# Generated by FakeRAM 2.0
VERSION 5.7 ;
BUSBITCHARS "[]" ;
PROPERTYDEFINITIONS
  MACRO width INTEGER ;
  MACRO depth INTEGER ;
  MACRO banks INTEGER ;
END PROPERTYDEFINITIONS
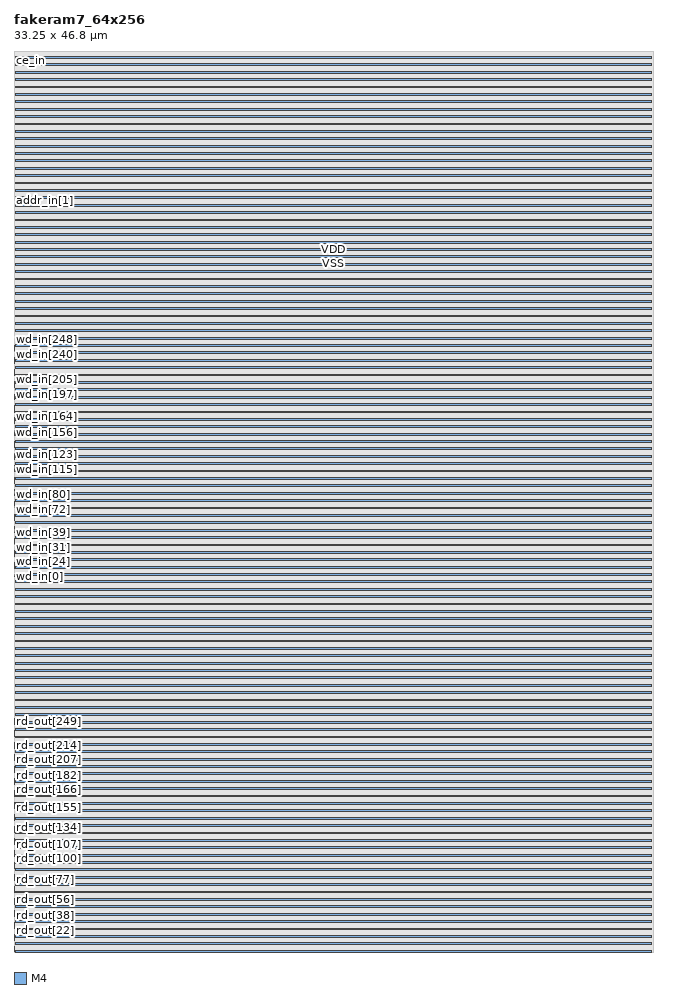
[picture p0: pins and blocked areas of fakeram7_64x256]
MACRO fakeram7_64x256
  PROPERTY width 256 ;
  PROPERTY depth 64 ;
  PROPERTY banks 1 ;
  FOREIGN fakeram7_64x256 0 0 ;
  SYMMETRY X Y R90 ;
  SIZE 33.250 BY 46.800 ;
  CLASS BLOCK ;
  PIN rd_out[0]
    DIRECTION OUTPUT ;
    USE SIGNAL ;
    SHAPE ABUTMENT ;
    PORT
      LAYER M4 ;
      RECT 0.000 0.048 0.036 0.072 ;
    END
  END rd_out[0]
  PIN rd_out[1]
    DIRECTION OUTPUT ;
    USE SIGNAL ;
    SHAPE ABUTMENT ;
    PORT
      LAYER M4 ;
      RECT 0.000 0.096 0.036 0.120 ;
    END
  END rd_out[1]
  PIN rd_out[2]
    DIRECTION OUTPUT ;
    USE SIGNAL ;
    SHAPE ABUTMENT ;
    PORT
      LAYER M4 ;
      RECT 0.000 0.144 0.036 0.168 ;
    END
  END rd_out[2]
  PIN rd_out[3]
    DIRECTION OUTPUT ;
    USE SIGNAL ;
    SHAPE ABUTMENT ;
    PORT
      LAYER M4 ;
      RECT 0.000 0.192 0.036 0.216 ;
    END
  END rd_out[3]
  PIN rd_out[4]
    DIRECTION OUTPUT ;
    USE SIGNAL ;
    SHAPE ABUTMENT ;
    PORT
      LAYER M4 ;
      RECT 0.000 0.240 0.036 0.264 ;
    END
  END rd_out[4]
  PIN rd_out[5]
    DIRECTION OUTPUT ;
    USE SIGNAL ;
    SHAPE ABUTMENT ;
    PORT
      LAYER M4 ;
      RECT 0.000 0.288 0.036 0.312 ;
    END
  END rd_out[5]
  PIN rd_out[6]
    DIRECTION OUTPUT ;
    USE SIGNAL ;
    SHAPE ABUTMENT ;
    PORT
      LAYER M4 ;
      RECT 0.000 0.336 0.036 0.360 ;
    END
  END rd_out[6]
  PIN rd_out[7]
    DIRECTION OUTPUT ;
    USE SIGNAL ;
    SHAPE ABUTMENT ;
    PORT
      LAYER M4 ;
      RECT 0.000 0.384 0.036 0.408 ;
    END
  END rd_out[7]
  PIN rd_out[8]
    DIRECTION OUTPUT ;
    USE SIGNAL ;
    SHAPE ABUTMENT ;
    PORT
      LAYER M4 ;
      RECT 0.000 0.432 0.036 0.456 ;
    END
  END rd_out[8]
  PIN rd_out[9]
    DIRECTION OUTPUT ;
    USE SIGNAL ;
    SHAPE ABUTMENT ;
    PORT
      LAYER M4 ;
      RECT 0.000 0.480 0.036 0.504 ;
    END
  END rd_out[9]
  PIN rd_out[10]
    DIRECTION OUTPUT ;
    USE SIGNAL ;
    SHAPE ABUTMENT ;
    PORT
      LAYER M4 ;
      RECT 0.000 0.528 0.036 0.552 ;
    END
  END rd_out[10]
  PIN rd_out[11]
    DIRECTION OUTPUT ;
    USE SIGNAL ;
    SHAPE ABUTMENT ;
    PORT
      LAYER M4 ;
      RECT 0.000 0.576 0.036 0.600 ;
    END
  END rd_out[11]
  PIN rd_out[12]
    DIRECTION OUTPUT ;
    USE SIGNAL ;
    SHAPE ABUTMENT ;
    PORT
      LAYER M4 ;
      RECT 0.000 0.624 0.036 0.648 ;
    END
  END rd_out[12]
  PIN rd_out[13]
    DIRECTION OUTPUT ;
    USE SIGNAL ;
    SHAPE ABUTMENT ;
    PORT
      LAYER M4 ;
      RECT 0.000 0.672 0.036 0.696 ;
    END
  END rd_out[13]
  PIN rd_out[14]
    DIRECTION OUTPUT ;
    USE SIGNAL ;
    SHAPE ABUTMENT ;
    PORT
      LAYER M4 ;
      RECT 0.000 0.720 0.036 0.744 ;
    END
  END rd_out[14]
  PIN rd_out[15]
    DIRECTION OUTPUT ;
    USE SIGNAL ;
    SHAPE ABUTMENT ;
    PORT
      LAYER M4 ;
      RECT 0.000 0.768 0.036 0.792 ;
    END
  END rd_out[15]
  PIN rd_out[16]
    DIRECTION OUTPUT ;
    USE SIGNAL ;
    SHAPE ABUTMENT ;
    PORT
      LAYER M4 ;
      RECT 0.000 0.816 0.036 0.840 ;
    END
  END rd_out[16]
  PIN rd_out[17]
    DIRECTION OUTPUT ;
    USE SIGNAL ;
    SHAPE ABUTMENT ;
    PORT
      LAYER M4 ;
      RECT 0.000 0.864 0.036 0.888 ;
    END
  END rd_out[17]
  PIN rd_out[18]
    DIRECTION OUTPUT ;
    USE SIGNAL ;
    SHAPE ABUTMENT ;
    PORT
      LAYER M4 ;
      RECT 0.000 0.912 0.036 0.936 ;
    END
  END rd_out[18]
  PIN rd_out[19]
    DIRECTION OUTPUT ;
    USE SIGNAL ;
    SHAPE ABUTMENT ;
    PORT
      LAYER M4 ;
      RECT 0.000 0.960 0.036 0.984 ;
    END
  END rd_out[19]
  PIN rd_out[20]
    DIRECTION OUTPUT ;
    USE SIGNAL ;
    SHAPE ABUTMENT ;
    PORT
      LAYER M4 ;
      RECT 0.000 1.008 0.036 1.032 ;
    END
  END rd_out[20]
  PIN rd_out[21]
    DIRECTION OUTPUT ;
    USE SIGNAL ;
    SHAPE ABUTMENT ;
    PORT
      LAYER M4 ;
      RECT 0.000 1.056 0.036 1.080 ;
    END
  END rd_out[21]
  PIN rd_out[22]
    DIRECTION OUTPUT ;
    USE SIGNAL ;
    SHAPE ABUTMENT ;
    PORT
      LAYER M4 ;
      RECT 0.000 1.104 0.036 1.128 ;
    END
  END rd_out[22]
  PIN rd_out[23]
    DIRECTION OUTPUT ;
    USE SIGNAL ;
    SHAPE ABUTMENT ;
    PORT
      LAYER M4 ;
      RECT 0.000 1.152 0.036 1.176 ;
    END
  END rd_out[23]
  PIN rd_out[24]
    DIRECTION OUTPUT ;
    USE SIGNAL ;
    SHAPE ABUTMENT ;
    PORT
      LAYER M4 ;
      RECT 0.000 1.200 0.036 1.224 ;
    END
  END rd_out[24]
  PIN rd_out[25]
    DIRECTION OUTPUT ;
    USE SIGNAL ;
    SHAPE ABUTMENT ;
    PORT
      LAYER M4 ;
      RECT 0.000 1.248 0.036 1.272 ;
    END
  END rd_out[25]
  PIN rd_out[26]
    DIRECTION OUTPUT ;
    USE SIGNAL ;
    SHAPE ABUTMENT ;
    PORT
      LAYER M4 ;
      RECT 0.000 1.296 0.036 1.320 ;
    END
  END rd_out[26]
  PIN rd_out[27]
    DIRECTION OUTPUT ;
    USE SIGNAL ;
    SHAPE ABUTMENT ;
    PORT
      LAYER M4 ;
      RECT 0.000 1.344 0.036 1.368 ;
    END
  END rd_out[27]
  PIN rd_out[28]
    DIRECTION OUTPUT ;
    USE SIGNAL ;
    SHAPE ABUTMENT ;
    PORT
      LAYER M4 ;
      RECT 0.000 1.392 0.036 1.416 ;
    END
  END rd_out[28]
  PIN rd_out[29]
    DIRECTION OUTPUT ;
    USE SIGNAL ;
    SHAPE ABUTMENT ;
    PORT
      LAYER M4 ;
      RECT 0.000 1.440 0.036 1.464 ;
    END
  END rd_out[29]
  PIN rd_out[30]
    DIRECTION OUTPUT ;
    USE SIGNAL ;
    SHAPE ABUTMENT ;
    PORT
      LAYER M4 ;
      RECT 0.000 1.488 0.036 1.512 ;
    END
  END rd_out[30]
  PIN rd_out[31]
    DIRECTION OUTPUT ;
    USE SIGNAL ;
    SHAPE ABUTMENT ;
    PORT
      LAYER M4 ;
      RECT 0.000 1.536 0.036 1.560 ;
    END
  END rd_out[31]
  PIN rd_out[32]
    DIRECTION OUTPUT ;
    USE SIGNAL ;
    SHAPE ABUTMENT ;
    PORT
      LAYER M4 ;
      RECT 0.000 1.584 0.036 1.608 ;
    END
  END rd_out[32]
  PIN rd_out[33]
    DIRECTION OUTPUT ;
    USE SIGNAL ;
    SHAPE ABUTMENT ;
    PORT
      LAYER M4 ;
      RECT 0.000 1.632 0.036 1.656 ;
    END
  END rd_out[33]
  PIN rd_out[34]
    DIRECTION OUTPUT ;
    USE SIGNAL ;
    SHAPE ABUTMENT ;
    PORT
      LAYER M4 ;
      RECT 0.000 1.680 0.036 1.704 ;
    END
  END rd_out[34]
  PIN rd_out[35]
    DIRECTION OUTPUT ;
    USE SIGNAL ;
    SHAPE ABUTMENT ;
    PORT
      LAYER M4 ;
      RECT 0.000 1.728 0.036 1.752 ;
    END
  END rd_out[35]
  PIN rd_out[36]
    DIRECTION OUTPUT ;
    USE SIGNAL ;
    SHAPE ABUTMENT ;
    PORT
      LAYER M4 ;
      RECT 0.000 1.776 0.036 1.800 ;
    END
  END rd_out[36]
  PIN rd_out[37]
    DIRECTION OUTPUT ;
    USE SIGNAL ;
    SHAPE ABUTMENT ;
    PORT
      LAYER M4 ;
      RECT 0.000 1.824 0.036 1.848 ;
    END
  END rd_out[37]
  PIN rd_out[38]
    DIRECTION OUTPUT ;
    USE SIGNAL ;
    SHAPE ABUTMENT ;
    PORT
      LAYER M4 ;
      RECT 0.000 1.872 0.036 1.896 ;
    END
  END rd_out[38]
  PIN rd_out[39]
    DIRECTION OUTPUT ;
    USE SIGNAL ;
    SHAPE ABUTMENT ;
    PORT
      LAYER M4 ;
      RECT 0.000 1.920 0.036 1.944 ;
    END
  END rd_out[39]
  PIN rd_out[40]
    DIRECTION OUTPUT ;
    USE SIGNAL ;
    SHAPE ABUTMENT ;
    PORT
      LAYER M4 ;
      RECT 0.000 1.968 0.036 1.992 ;
    END
  END rd_out[40]
  PIN rd_out[41]
    DIRECTION OUTPUT ;
    USE SIGNAL ;
    SHAPE ABUTMENT ;
    PORT
      LAYER M4 ;
      RECT 0.000 2.016 0.036 2.040 ;
    END
  END rd_out[41]
  PIN rd_out[42]
    DIRECTION OUTPUT ;
    USE SIGNAL ;
    SHAPE ABUTMENT ;
    PORT
      LAYER M4 ;
      RECT 0.000 2.064 0.036 2.088 ;
    END
  END rd_out[42]
  PIN rd_out[43]
    DIRECTION OUTPUT ;
    USE SIGNAL ;
    SHAPE ABUTMENT ;
    PORT
      LAYER M4 ;
      RECT 0.000 2.112 0.036 2.136 ;
    END
  END rd_out[43]
  PIN rd_out[44]
    DIRECTION OUTPUT ;
    USE SIGNAL ;
    SHAPE ABUTMENT ;
    PORT
      LAYER M4 ;
      RECT 0.000 2.160 0.036 2.184 ;
    END
  END rd_out[44]
  PIN rd_out[45]
    DIRECTION OUTPUT ;
    USE SIGNAL ;
    SHAPE ABUTMENT ;
    PORT
      LAYER M4 ;
      RECT 0.000 2.208 0.036 2.232 ;
    END
  END rd_out[45]
  PIN rd_out[46]
    DIRECTION OUTPUT ;
    USE SIGNAL ;
    SHAPE ABUTMENT ;
    PORT
      LAYER M4 ;
      RECT 0.000 2.256 0.036 2.280 ;
    END
  END rd_out[46]
  PIN rd_out[47]
    DIRECTION OUTPUT ;
    USE SIGNAL ;
    SHAPE ABUTMENT ;
    PORT
      LAYER M4 ;
      RECT 0.000 2.304 0.036 2.328 ;
    END
  END rd_out[47]
  PIN rd_out[48]
    DIRECTION OUTPUT ;
    USE SIGNAL ;
    SHAPE ABUTMENT ;
    PORT
      LAYER M4 ;
      RECT 0.000 2.352 0.036 2.376 ;
    END
  END rd_out[48]
  PIN rd_out[49]
    DIRECTION OUTPUT ;
    USE SIGNAL ;
    SHAPE ABUTMENT ;
    PORT
      LAYER M4 ;
      RECT 0.000 2.400 0.036 2.424 ;
    END
  END rd_out[49]
  PIN rd_out[50]
    DIRECTION OUTPUT ;
    USE SIGNAL ;
    SHAPE ABUTMENT ;
    PORT
      LAYER M4 ;
      RECT 0.000 2.448 0.036 2.472 ;
    END
  END rd_out[50]
  PIN rd_out[51]
    DIRECTION OUTPUT ;
    USE SIGNAL ;
    SHAPE ABUTMENT ;
    PORT
      LAYER M4 ;
      RECT 0.000 2.496 0.036 2.520 ;
    END
  END rd_out[51]
  PIN rd_out[52]
    DIRECTION OUTPUT ;
    USE SIGNAL ;
    SHAPE ABUTMENT ;
    PORT
      LAYER M4 ;
      RECT 0.000 2.544 0.036 2.568 ;
    END
  END rd_out[52]
  PIN rd_out[53]
    DIRECTION OUTPUT ;
    USE SIGNAL ;
    SHAPE ABUTMENT ;
    PORT
      LAYER M4 ;
      RECT 0.000 2.592 0.036 2.616 ;
    END
  END rd_out[53]
  PIN rd_out[54]
    DIRECTION OUTPUT ;
    USE SIGNAL ;
    SHAPE ABUTMENT ;
    PORT
      LAYER M4 ;
      RECT 0.000 2.640 0.036 2.664 ;
    END
  END rd_out[54]
  PIN rd_out[55]
    DIRECTION OUTPUT ;
    USE SIGNAL ;
    SHAPE ABUTMENT ;
    PORT
      LAYER M4 ;
      RECT 0.000 2.688 0.036 2.712 ;
    END
  END rd_out[55]
  PIN rd_out[56]
    DIRECTION OUTPUT ;
    USE SIGNAL ;
    SHAPE ABUTMENT ;
    PORT
      LAYER M4 ;
      RECT 0.000 2.736 0.036 2.760 ;
    END
  END rd_out[56]
  PIN rd_out[57]
    DIRECTION OUTPUT ;
    USE SIGNAL ;
    SHAPE ABUTMENT ;
    PORT
      LAYER M4 ;
      RECT 0.000 2.784 0.036 2.808 ;
    END
  END rd_out[57]
  PIN rd_out[58]
    DIRECTION OUTPUT ;
    USE SIGNAL ;
    SHAPE ABUTMENT ;
    PORT
      LAYER M4 ;
      RECT 0.000 2.832 0.036 2.856 ;
    END
  END rd_out[58]
  PIN rd_out[59]
    DIRECTION OUTPUT ;
    USE SIGNAL ;
    SHAPE ABUTMENT ;
    PORT
      LAYER M4 ;
      RECT 0.000 2.880 0.036 2.904 ;
    END
  END rd_out[59]
  PIN rd_out[60]
    DIRECTION OUTPUT ;
    USE SIGNAL ;
    SHAPE ABUTMENT ;
    PORT
      LAYER M4 ;
      RECT 0.000 2.928 0.036 2.952 ;
    END
  END rd_out[60]
  PIN rd_out[61]
    DIRECTION OUTPUT ;
    USE SIGNAL ;
    SHAPE ABUTMENT ;
    PORT
      LAYER M4 ;
      RECT 0.000 2.976 0.036 3.000 ;
    END
  END rd_out[61]
  PIN rd_out[62]
    DIRECTION OUTPUT ;
    USE SIGNAL ;
    SHAPE ABUTMENT ;
    PORT
      LAYER M4 ;
      RECT 0.000 3.024 0.036 3.048 ;
    END
  END rd_out[62]
  PIN rd_out[63]
    DIRECTION OUTPUT ;
    USE SIGNAL ;
    SHAPE ABUTMENT ;
    PORT
      LAYER M4 ;
      RECT 0.000 3.072 0.036 3.096 ;
    END
  END rd_out[63]
  PIN rd_out[64]
    DIRECTION OUTPUT ;
    USE SIGNAL ;
    SHAPE ABUTMENT ;
    PORT
      LAYER M4 ;
      RECT 0.000 3.120 0.036 3.144 ;
    END
  END rd_out[64]
  PIN rd_out[65]
    DIRECTION OUTPUT ;
    USE SIGNAL ;
    SHAPE ABUTMENT ;
    PORT
      LAYER M4 ;
      RECT 0.000 3.168 0.036 3.192 ;
    END
  END rd_out[65]
  PIN rd_out[66]
    DIRECTION OUTPUT ;
    USE SIGNAL ;
    SHAPE ABUTMENT ;
    PORT
      LAYER M4 ;
      RECT 0.000 3.216 0.036 3.240 ;
    END
  END rd_out[66]
  PIN rd_out[67]
    DIRECTION OUTPUT ;
    USE SIGNAL ;
    SHAPE ABUTMENT ;
    PORT
      LAYER M4 ;
      RECT 0.000 3.264 0.036 3.288 ;
    END
  END rd_out[67]
  PIN rd_out[68]
    DIRECTION OUTPUT ;
    USE SIGNAL ;
    SHAPE ABUTMENT ;
    PORT
      LAYER M4 ;
      RECT 0.000 3.312 0.036 3.336 ;
    END
  END rd_out[68]
  PIN rd_out[69]
    DIRECTION OUTPUT ;
    USE SIGNAL ;
    SHAPE ABUTMENT ;
    PORT
      LAYER M4 ;
      RECT 0.000 3.360 0.036 3.384 ;
    END
  END rd_out[69]
  PIN rd_out[70]
    DIRECTION OUTPUT ;
    USE SIGNAL ;
    SHAPE ABUTMENT ;
    PORT
      LAYER M4 ;
      RECT 0.000 3.408 0.036 3.432 ;
    END
  END rd_out[70]
  PIN rd_out[71]
    DIRECTION OUTPUT ;
    USE SIGNAL ;
    SHAPE ABUTMENT ;
    PORT
      LAYER M4 ;
      RECT 0.000 3.456 0.036 3.480 ;
    END
  END rd_out[71]
  PIN rd_out[72]
    DIRECTION OUTPUT ;
    USE SIGNAL ;
    SHAPE ABUTMENT ;
    PORT
      LAYER M4 ;
      RECT 0.000 3.504 0.036 3.528 ;
    END
  END rd_out[72]
  PIN rd_out[73]
    DIRECTION OUTPUT ;
    USE SIGNAL ;
    SHAPE ABUTMENT ;
    PORT
      LAYER M4 ;
      RECT 0.000 3.552 0.036 3.576 ;
    END
  END rd_out[73]
  PIN rd_out[74]
    DIRECTION OUTPUT ;
    USE SIGNAL ;
    SHAPE ABUTMENT ;
    PORT
      LAYER M4 ;
      RECT 0.000 3.600 0.036 3.624 ;
    END
  END rd_out[74]
  PIN rd_out[75]
    DIRECTION OUTPUT ;
    USE SIGNAL ;
    SHAPE ABUTMENT ;
    PORT
      LAYER M4 ;
      RECT 0.000 3.648 0.036 3.672 ;
    END
  END rd_out[75]
  PIN rd_out[76]
    DIRECTION OUTPUT ;
    USE SIGNAL ;
    SHAPE ABUTMENT ;
    PORT
      LAYER M4 ;
      RECT 0.000 3.696 0.036 3.720 ;
    END
  END rd_out[76]
  PIN rd_out[77]
    DIRECTION OUTPUT ;
    USE SIGNAL ;
    SHAPE ABUTMENT ;
    PORT
      LAYER M4 ;
      RECT 0.000 3.744 0.036 3.768 ;
    END
  END rd_out[77]
  PIN rd_out[78]
    DIRECTION OUTPUT ;
    USE SIGNAL ;
    SHAPE ABUTMENT ;
    PORT
      LAYER M4 ;
      RECT 0.000 3.792 0.036 3.816 ;
    END
  END rd_out[78]
  PIN rd_out[79]
    DIRECTION OUTPUT ;
    USE SIGNAL ;
    SHAPE ABUTMENT ;
    PORT
      LAYER M4 ;
      RECT 0.000 3.840 0.036 3.864 ;
    END
  END rd_out[79]
  PIN rd_out[80]
    DIRECTION OUTPUT ;
    USE SIGNAL ;
    SHAPE ABUTMENT ;
    PORT
      LAYER M4 ;
      RECT 0.000 3.888 0.036 3.912 ;
    END
  END rd_out[80]
  PIN rd_out[81]
    DIRECTION OUTPUT ;
    USE SIGNAL ;
    SHAPE ABUTMENT ;
    PORT
      LAYER M4 ;
      RECT 0.000 3.936 0.036 3.960 ;
    END
  END rd_out[81]
  PIN rd_out[82]
    DIRECTION OUTPUT ;
    USE SIGNAL ;
    SHAPE ABUTMENT ;
    PORT
      LAYER M4 ;
      RECT 0.000 3.984 0.036 4.008 ;
    END
  END rd_out[82]
  PIN rd_out[83]
    DIRECTION OUTPUT ;
    USE SIGNAL ;
    SHAPE ABUTMENT ;
    PORT
      LAYER M4 ;
      RECT 0.000 4.032 0.036 4.056 ;
    END
  END rd_out[83]
  PIN rd_out[84]
    DIRECTION OUTPUT ;
    USE SIGNAL ;
    SHAPE ABUTMENT ;
    PORT
      LAYER M4 ;
      RECT 0.000 4.080 0.036 4.104 ;
    END
  END rd_out[84]
  PIN rd_out[85]
    DIRECTION OUTPUT ;
    USE SIGNAL ;
    SHAPE ABUTMENT ;
    PORT
      LAYER M4 ;
      RECT 0.000 4.128 0.036 4.152 ;
    END
  END rd_out[85]
  PIN rd_out[86]
    DIRECTION OUTPUT ;
    USE SIGNAL ;
    SHAPE ABUTMENT ;
    PORT
      LAYER M4 ;
      RECT 0.000 4.176 0.036 4.200 ;
    END
  END rd_out[86]
  PIN rd_out[87]
    DIRECTION OUTPUT ;
    USE SIGNAL ;
    SHAPE ABUTMENT ;
    PORT
      LAYER M4 ;
      RECT 0.000 4.224 0.036 4.248 ;
    END
  END rd_out[87]
  PIN rd_out[88]
    DIRECTION OUTPUT ;
    USE SIGNAL ;
    SHAPE ABUTMENT ;
    PORT
      LAYER M4 ;
      RECT 0.000 4.272 0.036 4.296 ;
    END
  END rd_out[88]
  PIN rd_out[89]
    DIRECTION OUTPUT ;
    USE SIGNAL ;
    SHAPE ABUTMENT ;
    PORT
      LAYER M4 ;
      RECT 0.000 4.320 0.036 4.344 ;
    END
  END rd_out[89]
  PIN rd_out[90]
    DIRECTION OUTPUT ;
    USE SIGNAL ;
    SHAPE ABUTMENT ;
    PORT
      LAYER M4 ;
      RECT 0.000 4.368 0.036 4.392 ;
    END
  END rd_out[90]
  PIN rd_out[91]
    DIRECTION OUTPUT ;
    USE SIGNAL ;
    SHAPE ABUTMENT ;
    PORT
      LAYER M4 ;
      RECT 0.000 4.416 0.036 4.440 ;
    END
  END rd_out[91]
  PIN rd_out[92]
    DIRECTION OUTPUT ;
    USE SIGNAL ;
    SHAPE ABUTMENT ;
    PORT
      LAYER M4 ;
      RECT 0.000 4.464 0.036 4.488 ;
    END
  END rd_out[92]
  PIN rd_out[93]
    DIRECTION OUTPUT ;
    USE SIGNAL ;
    SHAPE ABUTMENT ;
    PORT
      LAYER M4 ;
      RECT 0.000 4.512 0.036 4.536 ;
    END
  END rd_out[93]
  PIN rd_out[94]
    DIRECTION OUTPUT ;
    USE SIGNAL ;
    SHAPE ABUTMENT ;
    PORT
      LAYER M4 ;
      RECT 0.000 4.560 0.036 4.584 ;
    END
  END rd_out[94]
  PIN rd_out[95]
    DIRECTION OUTPUT ;
    USE SIGNAL ;
    SHAPE ABUTMENT ;
    PORT
      LAYER M4 ;
      RECT 0.000 4.608 0.036 4.632 ;
    END
  END rd_out[95]
  PIN rd_out[96]
    DIRECTION OUTPUT ;
    USE SIGNAL ;
    SHAPE ABUTMENT ;
    PORT
      LAYER M4 ;
      RECT 0.000 4.656 0.036 4.680 ;
    END
  END rd_out[96]
  PIN rd_out[97]
    DIRECTION OUTPUT ;
    USE SIGNAL ;
    SHAPE ABUTMENT ;
    PORT
      LAYER M4 ;
      RECT 0.000 4.704 0.036 4.728 ;
    END
  END rd_out[97]
  PIN rd_out[98]
    DIRECTION OUTPUT ;
    USE SIGNAL ;
    SHAPE ABUTMENT ;
    PORT
      LAYER M4 ;
      RECT 0.000 4.752 0.036 4.776 ;
    END
  END rd_out[98]
  PIN rd_out[99]
    DIRECTION OUTPUT ;
    USE SIGNAL ;
    SHAPE ABUTMENT ;
    PORT
      LAYER M4 ;
      RECT 0.000 4.800 0.036 4.824 ;
    END
  END rd_out[99]
  PIN rd_out[100]
    DIRECTION OUTPUT ;
    USE SIGNAL ;
    SHAPE ABUTMENT ;
    PORT
      LAYER M4 ;
      RECT 0.000 4.848 0.036 4.872 ;
    END
  END rd_out[100]
  PIN rd_out[101]
    DIRECTION OUTPUT ;
    USE SIGNAL ;
    SHAPE ABUTMENT ;
    PORT
      LAYER M4 ;
      RECT 0.000 4.896 0.036 4.920 ;
    END
  END rd_out[101]
  PIN rd_out[102]
    DIRECTION OUTPUT ;
    USE SIGNAL ;
    SHAPE ABUTMENT ;
    PORT
      LAYER M4 ;
      RECT 0.000 4.944 0.036 4.968 ;
    END
  END rd_out[102]
  PIN rd_out[103]
    DIRECTION OUTPUT ;
    USE SIGNAL ;
    SHAPE ABUTMENT ;
    PORT
      LAYER M4 ;
      RECT 0.000 4.992 0.036 5.016 ;
    END
  END rd_out[103]
  PIN rd_out[104]
    DIRECTION OUTPUT ;
    USE SIGNAL ;
    SHAPE ABUTMENT ;
    PORT
      LAYER M4 ;
      RECT 0.000 5.040 0.036 5.064 ;
    END
  END rd_out[104]
  PIN rd_out[105]
    DIRECTION OUTPUT ;
    USE SIGNAL ;
    SHAPE ABUTMENT ;
    PORT
      LAYER M4 ;
      RECT 0.000 5.088 0.036 5.112 ;
    END
  END rd_out[105]
  PIN rd_out[106]
    DIRECTION OUTPUT ;
    USE SIGNAL ;
    SHAPE ABUTMENT ;
    PORT
      LAYER M4 ;
      RECT 0.000 5.136 0.036 5.160 ;
    END
  END rd_out[106]
  PIN rd_out[107]
    DIRECTION OUTPUT ;
    USE SIGNAL ;
    SHAPE ABUTMENT ;
    PORT
      LAYER M4 ;
      RECT 0.000 5.184 0.036 5.208 ;
    END
  END rd_out[107]
  PIN rd_out[108]
    DIRECTION OUTPUT ;
    USE SIGNAL ;
    SHAPE ABUTMENT ;
    PORT
      LAYER M4 ;
      RECT 0.000 5.232 0.036 5.256 ;
    END
  END rd_out[108]
  PIN rd_out[109]
    DIRECTION OUTPUT ;
    USE SIGNAL ;
    SHAPE ABUTMENT ;
    PORT
      LAYER M4 ;
      RECT 0.000 5.280 0.036 5.304 ;
    END
  END rd_out[109]
  PIN rd_out[110]
    DIRECTION OUTPUT ;
    USE SIGNAL ;
    SHAPE ABUTMENT ;
    PORT
      LAYER M4 ;
      RECT 0.000 5.328 0.036 5.352 ;
    END
  END rd_out[110]
  PIN rd_out[111]
    DIRECTION OUTPUT ;
    USE SIGNAL ;
    SHAPE ABUTMENT ;
    PORT
      LAYER M4 ;
      RECT 0.000 5.376 0.036 5.400 ;
    END
  END rd_out[111]
  PIN rd_out[112]
    DIRECTION OUTPUT ;
    USE SIGNAL ;
    SHAPE ABUTMENT ;
    PORT
      LAYER M4 ;
      RECT 0.000 5.424 0.036 5.448 ;
    END
  END rd_out[112]
  PIN rd_out[113]
    DIRECTION OUTPUT ;
    USE SIGNAL ;
    SHAPE ABUTMENT ;
    PORT
      LAYER M4 ;
      RECT 0.000 5.472 0.036 5.496 ;
    END
  END rd_out[113]
  PIN rd_out[114]
    DIRECTION OUTPUT ;
    USE SIGNAL ;
    SHAPE ABUTMENT ;
    PORT
      LAYER M4 ;
      RECT 0.000 5.520 0.036 5.544 ;
    END
  END rd_out[114]
  PIN rd_out[115]
    DIRECTION OUTPUT ;
    USE SIGNAL ;
    SHAPE ABUTMENT ;
    PORT
      LAYER M4 ;
      RECT 0.000 5.568 0.036 5.592 ;
    END
  END rd_out[115]
  PIN rd_out[116]
    DIRECTION OUTPUT ;
    USE SIGNAL ;
    SHAPE ABUTMENT ;
    PORT
      LAYER M4 ;
      RECT 0.000 5.616 0.036 5.640 ;
    END
  END rd_out[116]
  PIN rd_out[117]
    DIRECTION OUTPUT ;
    USE SIGNAL ;
    SHAPE ABUTMENT ;
    PORT
      LAYER M4 ;
      RECT 0.000 5.664 0.036 5.688 ;
    END
  END rd_out[117]
  PIN rd_out[118]
    DIRECTION OUTPUT ;
    USE SIGNAL ;
    SHAPE ABUTMENT ;
    PORT
      LAYER M4 ;
      RECT 0.000 5.712 0.036 5.736 ;
    END
  END rd_out[118]
  PIN rd_out[119]
    DIRECTION OUTPUT ;
    USE SIGNAL ;
    SHAPE ABUTMENT ;
    PORT
      LAYER M4 ;
      RECT 0.000 5.760 0.036 5.784 ;
    END
  END rd_out[119]
  PIN rd_out[120]
    DIRECTION OUTPUT ;
    USE SIGNAL ;
    SHAPE ABUTMENT ;
    PORT
      LAYER M4 ;
      RECT 0.000 5.808 0.036 5.832 ;
    END
  END rd_out[120]
  PIN rd_out[121]
    DIRECTION OUTPUT ;
    USE SIGNAL ;
    SHAPE ABUTMENT ;
    PORT
      LAYER M4 ;
      RECT 0.000 5.856 0.036 5.880 ;
    END
  END rd_out[121]
  PIN rd_out[122]
    DIRECTION OUTPUT ;
    USE SIGNAL ;
    SHAPE ABUTMENT ;
    PORT
      LAYER M4 ;
      RECT 0.000 5.904 0.036 5.928 ;
    END
  END rd_out[122]
  PIN rd_out[123]
    DIRECTION OUTPUT ;
    USE SIGNAL ;
    SHAPE ABUTMENT ;
    PORT
      LAYER M4 ;
      RECT 0.000 5.952 0.036 5.976 ;
    END
  END rd_out[123]
  PIN rd_out[124]
    DIRECTION OUTPUT ;
    USE SIGNAL ;
    SHAPE ABUTMENT ;
    PORT
      LAYER M4 ;
      RECT 0.000 6.000 0.036 6.024 ;
    END
  END rd_out[124]
  PIN rd_out[125]
    DIRECTION OUTPUT ;
    USE SIGNAL ;
    SHAPE ABUTMENT ;
    PORT
      LAYER M4 ;
      RECT 0.000 6.048 0.036 6.072 ;
    END
  END rd_out[125]
  PIN rd_out[126]
    DIRECTION OUTPUT ;
    USE SIGNAL ;
    SHAPE ABUTMENT ;
    PORT
      LAYER M4 ;
      RECT 0.000 6.096 0.036 6.120 ;
    END
  END rd_out[126]
  PIN rd_out[127]
    DIRECTION OUTPUT ;
    USE SIGNAL ;
    SHAPE ABUTMENT ;
    PORT
      LAYER M4 ;
      RECT 0.000 6.144 0.036 6.168 ;
    END
  END rd_out[127]
  PIN rd_out[128]
    DIRECTION OUTPUT ;
    USE SIGNAL ;
    SHAPE ABUTMENT ;
    PORT
      LAYER M4 ;
      RECT 0.000 6.192 0.036 6.216 ;
    END
  END rd_out[128]
  PIN rd_out[129]
    DIRECTION OUTPUT ;
    USE SIGNAL ;
    SHAPE ABUTMENT ;
    PORT
      LAYER M4 ;
      RECT 0.000 6.240 0.036 6.264 ;
    END
  END rd_out[129]
  PIN rd_out[130]
    DIRECTION OUTPUT ;
    USE SIGNAL ;
    SHAPE ABUTMENT ;
    PORT
      LAYER M4 ;
      RECT 0.000 6.288 0.036 6.312 ;
    END
  END rd_out[130]
  PIN rd_out[131]
    DIRECTION OUTPUT ;
    USE SIGNAL ;
    SHAPE ABUTMENT ;
    PORT
      LAYER M4 ;
      RECT 0.000 6.336 0.036 6.360 ;
    END
  END rd_out[131]
  PIN rd_out[132]
    DIRECTION OUTPUT ;
    USE SIGNAL ;
    SHAPE ABUTMENT ;
    PORT
      LAYER M4 ;
      RECT 0.000 6.384 0.036 6.408 ;
    END
  END rd_out[132]
  PIN rd_out[133]
    DIRECTION OUTPUT ;
    USE SIGNAL ;
    SHAPE ABUTMENT ;
    PORT
      LAYER M4 ;
      RECT 0.000 6.432 0.036 6.456 ;
    END
  END rd_out[133]
  PIN rd_out[134]
    DIRECTION OUTPUT ;
    USE SIGNAL ;
    SHAPE ABUTMENT ;
    PORT
      LAYER M4 ;
      RECT 0.000 6.480 0.036 6.504 ;
    END
  END rd_out[134]
  PIN rd_out[135]
    DIRECTION OUTPUT ;
    USE SIGNAL ;
    SHAPE ABUTMENT ;
    PORT
      LAYER M4 ;
      RECT 0.000 6.528 0.036 6.552 ;
    END
  END rd_out[135]
  PIN rd_out[136]
    DIRECTION OUTPUT ;
    USE SIGNAL ;
    SHAPE ABUTMENT ;
    PORT
      LAYER M4 ;
      RECT 0.000 6.576 0.036 6.600 ;
    END
  END rd_out[136]
  PIN rd_out[137]
    DIRECTION OUTPUT ;
    USE SIGNAL ;
    SHAPE ABUTMENT ;
    PORT
      LAYER M4 ;
      RECT 0.000 6.624 0.036 6.648 ;
    END
  END rd_out[137]
  PIN rd_out[138]
    DIRECTION OUTPUT ;
    USE SIGNAL ;
    SHAPE ABUTMENT ;
    PORT
      LAYER M4 ;
      RECT 0.000 6.672 0.036 6.696 ;
    END
  END rd_out[138]
  PIN rd_out[139]
    DIRECTION OUTPUT ;
    USE SIGNAL ;
    SHAPE ABUTMENT ;
    PORT
      LAYER M4 ;
      RECT 0.000 6.720 0.036 6.744 ;
    END
  END rd_out[139]
  PIN rd_out[140]
    DIRECTION OUTPUT ;
    USE SIGNAL ;
    SHAPE ABUTMENT ;
    PORT
      LAYER M4 ;
      RECT 0.000 6.768 0.036 6.792 ;
    END
  END rd_out[140]
  PIN rd_out[141]
    DIRECTION OUTPUT ;
    USE SIGNAL ;
    SHAPE ABUTMENT ;
    PORT
      LAYER M4 ;
      RECT 0.000 6.816 0.036 6.840 ;
    END
  END rd_out[141]
  PIN rd_out[142]
    DIRECTION OUTPUT ;
    USE SIGNAL ;
    SHAPE ABUTMENT ;
    PORT
      LAYER M4 ;
      RECT 0.000 6.864 0.036 6.888 ;
    END
  END rd_out[142]
  PIN rd_out[143]
    DIRECTION OUTPUT ;
    USE SIGNAL ;
    SHAPE ABUTMENT ;
    PORT
      LAYER M4 ;
      RECT 0.000 6.912 0.036 6.936 ;
    END
  END rd_out[143]
  PIN rd_out[144]
    DIRECTION OUTPUT ;
    USE SIGNAL ;
    SHAPE ABUTMENT ;
    PORT
      LAYER M4 ;
      RECT 0.000 6.960 0.036 6.984 ;
    END
  END rd_out[144]
  PIN rd_out[145]
    DIRECTION OUTPUT ;
    USE SIGNAL ;
    SHAPE ABUTMENT ;
    PORT
      LAYER M4 ;
      RECT 0.000 7.008 0.036 7.032 ;
    END
  END rd_out[145]
  PIN rd_out[146]
    DIRECTION OUTPUT ;
    USE SIGNAL ;
    SHAPE ABUTMENT ;
    PORT
      LAYER M4 ;
      RECT 0.000 7.056 0.036 7.080 ;
    END
  END rd_out[146]
  PIN rd_out[147]
    DIRECTION OUTPUT ;
    USE SIGNAL ;
    SHAPE ABUTMENT ;
    PORT
      LAYER M4 ;
      RECT 0.000 7.104 0.036 7.128 ;
    END
  END rd_out[147]
  PIN rd_out[148]
    DIRECTION OUTPUT ;
    USE SIGNAL ;
    SHAPE ABUTMENT ;
    PORT
      LAYER M4 ;
      RECT 0.000 7.152 0.036 7.176 ;
    END
  END rd_out[148]
  PIN rd_out[149]
    DIRECTION OUTPUT ;
    USE SIGNAL ;
    SHAPE ABUTMENT ;
    PORT
      LAYER M4 ;
      RECT 0.000 7.200 0.036 7.224 ;
    END
  END rd_out[149]
  PIN rd_out[150]
    DIRECTION OUTPUT ;
    USE SIGNAL ;
    SHAPE ABUTMENT ;
    PORT
      LAYER M4 ;
      RECT 0.000 7.248 0.036 7.272 ;
    END
  END rd_out[150]
  PIN rd_out[151]
    DIRECTION OUTPUT ;
    USE SIGNAL ;
    SHAPE ABUTMENT ;
    PORT
      LAYER M4 ;
      RECT 0.000 7.296 0.036 7.320 ;
    END
  END rd_out[151]
  PIN rd_out[152]
    DIRECTION OUTPUT ;
    USE SIGNAL ;
    SHAPE ABUTMENT ;
    PORT
      LAYER M4 ;
      RECT 0.000 7.344 0.036 7.368 ;
    END
  END rd_out[152]
  PIN rd_out[153]
    DIRECTION OUTPUT ;
    USE SIGNAL ;
    SHAPE ABUTMENT ;
    PORT
      LAYER M4 ;
      RECT 0.000 7.392 0.036 7.416 ;
    END
  END rd_out[153]
  PIN rd_out[154]
    DIRECTION OUTPUT ;
    USE SIGNAL ;
    SHAPE ABUTMENT ;
    PORT
      LAYER M4 ;
      RECT 0.000 7.440 0.036 7.464 ;
    END
  END rd_out[154]
  PIN rd_out[155]
    DIRECTION OUTPUT ;
    USE SIGNAL ;
    SHAPE ABUTMENT ;
    PORT
      LAYER M4 ;
      RECT 0.000 7.488 0.036 7.512 ;
    END
  END rd_out[155]
  PIN rd_out[156]
    DIRECTION OUTPUT ;
    USE SIGNAL ;
    SHAPE ABUTMENT ;
    PORT
      LAYER M4 ;
      RECT 0.000 7.536 0.036 7.560 ;
    END
  END rd_out[156]
  PIN rd_out[157]
    DIRECTION OUTPUT ;
    USE SIGNAL ;
    SHAPE ABUTMENT ;
    PORT
      LAYER M4 ;
      RECT 0.000 7.584 0.036 7.608 ;
    END
  END rd_out[157]
  PIN rd_out[158]
    DIRECTION OUTPUT ;
    USE SIGNAL ;
    SHAPE ABUTMENT ;
    PORT
      LAYER M4 ;
      RECT 0.000 7.632 0.036 7.656 ;
    END
  END rd_out[158]
  PIN rd_out[159]
    DIRECTION OUTPUT ;
    USE SIGNAL ;
    SHAPE ABUTMENT ;
    PORT
      LAYER M4 ;
      RECT 0.000 7.680 0.036 7.704 ;
    END
  END rd_out[159]
  PIN rd_out[160]
    DIRECTION OUTPUT ;
    USE SIGNAL ;
    SHAPE ABUTMENT ;
    PORT
      LAYER M4 ;
      RECT 0.000 7.728 0.036 7.752 ;
    END
  END rd_out[160]
  PIN rd_out[161]
    DIRECTION OUTPUT ;
    USE SIGNAL ;
    SHAPE ABUTMENT ;
    PORT
      LAYER M4 ;
      RECT 0.000 7.776 0.036 7.800 ;
    END
  END rd_out[161]
  PIN rd_out[162]
    DIRECTION OUTPUT ;
    USE SIGNAL ;
    SHAPE ABUTMENT ;
    PORT
      LAYER M4 ;
      RECT 0.000 7.824 0.036 7.848 ;
    END
  END rd_out[162]
  PIN rd_out[163]
    DIRECTION OUTPUT ;
    USE SIGNAL ;
    SHAPE ABUTMENT ;
    PORT
      LAYER M4 ;
      RECT 0.000 7.872 0.036 7.896 ;
    END
  END rd_out[163]
  PIN rd_out[164]
    DIRECTION OUTPUT ;
    USE SIGNAL ;
    SHAPE ABUTMENT ;
    PORT
      LAYER M4 ;
      RECT 0.000 7.920 0.036 7.944 ;
    END
  END rd_out[164]
  PIN rd_out[165]
    DIRECTION OUTPUT ;
    USE SIGNAL ;
    SHAPE ABUTMENT ;
    PORT
      LAYER M4 ;
      RECT 0.000 7.968 0.036 7.992 ;
    END
  END rd_out[165]
  PIN rd_out[166]
    DIRECTION OUTPUT ;
    USE SIGNAL ;
    SHAPE ABUTMENT ;
    PORT
      LAYER M4 ;
      RECT 0.000 8.016 0.036 8.040 ;
    END
  END rd_out[166]
  PIN rd_out[167]
    DIRECTION OUTPUT ;
    USE SIGNAL ;
    SHAPE ABUTMENT ;
    PORT
      LAYER M4 ;
      RECT 0.000 8.064 0.036 8.088 ;
    END
  END rd_out[167]
  PIN rd_out[168]
    DIRECTION OUTPUT ;
    USE SIGNAL ;
    SHAPE ABUTMENT ;
    PORT
      LAYER M4 ;
      RECT 0.000 8.112 0.036 8.136 ;
    END
  END rd_out[168]
  PIN rd_out[169]
    DIRECTION OUTPUT ;
    USE SIGNAL ;
    SHAPE ABUTMENT ;
    PORT
      LAYER M4 ;
      RECT 0.000 8.160 0.036 8.184 ;
    END
  END rd_out[169]
  PIN rd_out[170]
    DIRECTION OUTPUT ;
    USE SIGNAL ;
    SHAPE ABUTMENT ;
    PORT
      LAYER M4 ;
      RECT 0.000 8.208 0.036 8.232 ;
    END
  END rd_out[170]
  PIN rd_out[171]
    DIRECTION OUTPUT ;
    USE SIGNAL ;
    SHAPE ABUTMENT ;
    PORT
      LAYER M4 ;
      RECT 0.000 8.256 0.036 8.280 ;
    END
  END rd_out[171]
  PIN rd_out[172]
    DIRECTION OUTPUT ;
    USE SIGNAL ;
    SHAPE ABUTMENT ;
    PORT
      LAYER M4 ;
      RECT 0.000 8.304 0.036 8.328 ;
    END
  END rd_out[172]
  PIN rd_out[173]
    DIRECTION OUTPUT ;
    USE SIGNAL ;
    SHAPE ABUTMENT ;
    PORT
      LAYER M4 ;
      RECT 0.000 8.352 0.036 8.376 ;
    END
  END rd_out[173]
  PIN rd_out[174]
    DIRECTION OUTPUT ;
    USE SIGNAL ;
    SHAPE ABUTMENT ;
    PORT
      LAYER M4 ;
      RECT 0.000 8.400 0.036 8.424 ;
    END
  END rd_out[174]
  PIN rd_out[175]
    DIRECTION OUTPUT ;
    USE SIGNAL ;
    SHAPE ABUTMENT ;
    PORT
      LAYER M4 ;
      RECT 0.000 8.448 0.036 8.472 ;
    END
  END rd_out[175]
  PIN rd_out[176]
    DIRECTION OUTPUT ;
    USE SIGNAL ;
    SHAPE ABUTMENT ;
    PORT
      LAYER M4 ;
      RECT 0.000 8.496 0.036 8.520 ;
    END
  END rd_out[176]
  PIN rd_out[177]
    DIRECTION OUTPUT ;
    USE SIGNAL ;
    SHAPE ABUTMENT ;
    PORT
      LAYER M4 ;
      RECT 0.000 8.544 0.036 8.568 ;
    END
  END rd_out[177]
  PIN rd_out[178]
    DIRECTION OUTPUT ;
    USE SIGNAL ;
    SHAPE ABUTMENT ;
    PORT
      LAYER M4 ;
      RECT 0.000 8.592 0.036 8.616 ;
    END
  END rd_out[178]
  PIN rd_out[179]
    DIRECTION OUTPUT ;
    USE SIGNAL ;
    SHAPE ABUTMENT ;
    PORT
      LAYER M4 ;
      RECT 0.000 8.640 0.036 8.664 ;
    END
  END rd_out[179]
  PIN rd_out[180]
    DIRECTION OUTPUT ;
    USE SIGNAL ;
    SHAPE ABUTMENT ;
    PORT
      LAYER M4 ;
      RECT 0.000 8.688 0.036 8.712 ;
    END
  END rd_out[180]
  PIN rd_out[181]
    DIRECTION OUTPUT ;
    USE SIGNAL ;
    SHAPE ABUTMENT ;
    PORT
      LAYER M4 ;
      RECT 0.000 8.736 0.036 8.760 ;
    END
  END rd_out[181]
  PIN rd_out[182]
    DIRECTION OUTPUT ;
    USE SIGNAL ;
    SHAPE ABUTMENT ;
    PORT
      LAYER M4 ;
      RECT 0.000 8.784 0.036 8.808 ;
    END
  END rd_out[182]
  PIN rd_out[183]
    DIRECTION OUTPUT ;
    USE SIGNAL ;
    SHAPE ABUTMENT ;
    PORT
      LAYER M4 ;
      RECT 0.000 8.832 0.036 8.856 ;
    END
  END rd_out[183]
  PIN rd_out[184]
    DIRECTION OUTPUT ;
    USE SIGNAL ;
    SHAPE ABUTMENT ;
    PORT
      LAYER M4 ;
      RECT 0.000 8.880 0.036 8.904 ;
    END
  END rd_out[184]
  PIN rd_out[185]
    DIRECTION OUTPUT ;
    USE SIGNAL ;
    SHAPE ABUTMENT ;
    PORT
      LAYER M4 ;
      RECT 0.000 8.928 0.036 8.952 ;
    END
  END rd_out[185]
  PIN rd_out[186]
    DIRECTION OUTPUT ;
    USE SIGNAL ;
    SHAPE ABUTMENT ;
    PORT
      LAYER M4 ;
      RECT 0.000 8.976 0.036 9.000 ;
    END
  END rd_out[186]
  PIN rd_out[187]
    DIRECTION OUTPUT ;
    USE SIGNAL ;
    SHAPE ABUTMENT ;
    PORT
      LAYER M4 ;
      RECT 0.000 9.024 0.036 9.048 ;
    END
  END rd_out[187]
  PIN rd_out[188]
    DIRECTION OUTPUT ;
    USE SIGNAL ;
    SHAPE ABUTMENT ;
    PORT
      LAYER M4 ;
      RECT 0.000 9.072 0.036 9.096 ;
    END
  END rd_out[188]
  PIN rd_out[189]
    DIRECTION OUTPUT ;
    USE SIGNAL ;
    SHAPE ABUTMENT ;
    PORT
      LAYER M4 ;
      RECT 0.000 9.120 0.036 9.144 ;
    END
  END rd_out[189]
  PIN rd_out[190]
    DIRECTION OUTPUT ;
    USE SIGNAL ;
    SHAPE ABUTMENT ;
    PORT
      LAYER M4 ;
      RECT 0.000 9.168 0.036 9.192 ;
    END
  END rd_out[190]
  PIN rd_out[191]
    DIRECTION OUTPUT ;
    USE SIGNAL ;
    SHAPE ABUTMENT ;
    PORT
      LAYER M4 ;
      RECT 0.000 9.216 0.036 9.240 ;
    END
  END rd_out[191]
  PIN rd_out[192]
    DIRECTION OUTPUT ;
    USE SIGNAL ;
    SHAPE ABUTMENT ;
    PORT
      LAYER M4 ;
      RECT 0.000 9.264 0.036 9.288 ;
    END
  END rd_out[192]
  PIN rd_out[193]
    DIRECTION OUTPUT ;
    USE SIGNAL ;
    SHAPE ABUTMENT ;
    PORT
      LAYER M4 ;
      RECT 0.000 9.312 0.036 9.336 ;
    END
  END rd_out[193]
  PIN rd_out[194]
    DIRECTION OUTPUT ;
    USE SIGNAL ;
    SHAPE ABUTMENT ;
    PORT
      LAYER M4 ;
      RECT 0.000 9.360 0.036 9.384 ;
    END
  END rd_out[194]
  PIN rd_out[195]
    DIRECTION OUTPUT ;
    USE SIGNAL ;
    SHAPE ABUTMENT ;
    PORT
      LAYER M4 ;
      RECT 0.000 9.408 0.036 9.432 ;
    END
  END rd_out[195]
  PIN rd_out[196]
    DIRECTION OUTPUT ;
    USE SIGNAL ;
    SHAPE ABUTMENT ;
    PORT
      LAYER M4 ;
      RECT 0.000 9.456 0.036 9.480 ;
    END
  END rd_out[196]
  PIN rd_out[197]
    DIRECTION OUTPUT ;
    USE SIGNAL ;
    SHAPE ABUTMENT ;
    PORT
      LAYER M4 ;
      RECT 0.000 9.504 0.036 9.528 ;
    END
  END rd_out[197]
  PIN rd_out[198]
    DIRECTION OUTPUT ;
    USE SIGNAL ;
    SHAPE ABUTMENT ;
    PORT
      LAYER M4 ;
      RECT 0.000 9.552 0.036 9.576 ;
    END
  END rd_out[198]
  PIN rd_out[199]
    DIRECTION OUTPUT ;
    USE SIGNAL ;
    SHAPE ABUTMENT ;
    PORT
      LAYER M4 ;
      RECT 0.000 9.600 0.036 9.624 ;
    END
  END rd_out[199]
  PIN rd_out[200]
    DIRECTION OUTPUT ;
    USE SIGNAL ;
    SHAPE ABUTMENT ;
    PORT
      LAYER M4 ;
      RECT 0.000 9.648 0.036 9.672 ;
    END
  END rd_out[200]
  PIN rd_out[201]
    DIRECTION OUTPUT ;
    USE SIGNAL ;
    SHAPE ABUTMENT ;
    PORT
      LAYER M4 ;
      RECT 0.000 9.696 0.036 9.720 ;
    END
  END rd_out[201]
  PIN rd_out[202]
    DIRECTION OUTPUT ;
    USE SIGNAL ;
    SHAPE ABUTMENT ;
    PORT
      LAYER M4 ;
      RECT 0.000 9.744 0.036 9.768 ;
    END
  END rd_out[202]
  PIN rd_out[203]
    DIRECTION OUTPUT ;
    USE SIGNAL ;
    SHAPE ABUTMENT ;
    PORT
      LAYER M4 ;
      RECT 0.000 9.792 0.036 9.816 ;
    END
  END rd_out[203]
  PIN rd_out[204]
    DIRECTION OUTPUT ;
    USE SIGNAL ;
    SHAPE ABUTMENT ;
    PORT
      LAYER M4 ;
      RECT 0.000 9.840 0.036 9.864 ;
    END
  END rd_out[204]
  PIN rd_out[205]
    DIRECTION OUTPUT ;
    USE SIGNAL ;
    SHAPE ABUTMENT ;
    PORT
      LAYER M4 ;
      RECT 0.000 9.888 0.036 9.912 ;
    END
  END rd_out[205]
  PIN rd_out[206]
    DIRECTION OUTPUT ;
    USE SIGNAL ;
    SHAPE ABUTMENT ;
    PORT
      LAYER M4 ;
      RECT 0.000 9.936 0.036 9.960 ;
    END
  END rd_out[206]
  PIN rd_out[207]
    DIRECTION OUTPUT ;
    USE SIGNAL ;
    SHAPE ABUTMENT ;
    PORT
      LAYER M4 ;
      RECT 0.000 9.984 0.036 10.008 ;
    END
  END rd_out[207]
  PIN rd_out[208]
    DIRECTION OUTPUT ;
    USE SIGNAL ;
    SHAPE ABUTMENT ;
    PORT
      LAYER M4 ;
      RECT 0.000 10.032 0.036 10.056 ;
    END
  END rd_out[208]
  PIN rd_out[209]
    DIRECTION OUTPUT ;
    USE SIGNAL ;
    SHAPE ABUTMENT ;
    PORT
      LAYER M4 ;
      RECT 0.000 10.080 0.036 10.104 ;
    END
  END rd_out[209]
  PIN rd_out[210]
    DIRECTION OUTPUT ;
    USE SIGNAL ;
    SHAPE ABUTMENT ;
    PORT
      LAYER M4 ;
      RECT 0.000 10.128 0.036 10.152 ;
    END
  END rd_out[210]
  PIN rd_out[211]
    DIRECTION OUTPUT ;
    USE SIGNAL ;
    SHAPE ABUTMENT ;
    PORT
      LAYER M4 ;
      RECT 0.000 10.176 0.036 10.200 ;
    END
  END rd_out[211]
  PIN rd_out[212]
    DIRECTION OUTPUT ;
    USE SIGNAL ;
    SHAPE ABUTMENT ;
    PORT
      LAYER M4 ;
      RECT 0.000 10.224 0.036 10.248 ;
    END
  END rd_out[212]
  PIN rd_out[213]
    DIRECTION OUTPUT ;
    USE SIGNAL ;
    SHAPE ABUTMENT ;
    PORT
      LAYER M4 ;
      RECT 0.000 10.272 0.036 10.296 ;
    END
  END rd_out[213]
  PIN rd_out[214]
    DIRECTION OUTPUT ;
    USE SIGNAL ;
    SHAPE ABUTMENT ;
    PORT
      LAYER M4 ;
      RECT 0.000 10.320 0.036 10.344 ;
    END
  END rd_out[214]
  PIN rd_out[215]
    DIRECTION OUTPUT ;
    USE SIGNAL ;
    SHAPE ABUTMENT ;
    PORT
      LAYER M4 ;
      RECT 0.000 10.368 0.036 10.392 ;
    END
  END rd_out[215]
  PIN rd_out[216]
    DIRECTION OUTPUT ;
    USE SIGNAL ;
    SHAPE ABUTMENT ;
    PORT
      LAYER M4 ;
      RECT 0.000 10.416 0.036 10.440 ;
    END
  END rd_out[216]
  PIN rd_out[217]
    DIRECTION OUTPUT ;
    USE SIGNAL ;
    SHAPE ABUTMENT ;
    PORT
      LAYER M4 ;
      RECT 0.000 10.464 0.036 10.488 ;
    END
  END rd_out[217]
  PIN rd_out[218]
    DIRECTION OUTPUT ;
    USE SIGNAL ;
    SHAPE ABUTMENT ;
    PORT
      LAYER M4 ;
      RECT 0.000 10.512 0.036 10.536 ;
    END
  END rd_out[218]
  PIN rd_out[219]
    DIRECTION OUTPUT ;
    USE SIGNAL ;
    SHAPE ABUTMENT ;
    PORT
      LAYER M4 ;
      RECT 0.000 10.560 0.036 10.584 ;
    END
  END rd_out[219]
  PIN rd_out[220]
    DIRECTION OUTPUT ;
    USE SIGNAL ;
    SHAPE ABUTMENT ;
    PORT
      LAYER M4 ;
      RECT 0.000 10.608 0.036 10.632 ;
    END
  END rd_out[220]
  PIN rd_out[221]
    DIRECTION OUTPUT ;
    USE SIGNAL ;
    SHAPE ABUTMENT ;
    PORT
      LAYER M4 ;
      RECT 0.000 10.656 0.036 10.680 ;
    END
  END rd_out[221]
  PIN rd_out[222]
    DIRECTION OUTPUT ;
    USE SIGNAL ;
    SHAPE ABUTMENT ;
    PORT
      LAYER M4 ;
      RECT 0.000 10.704 0.036 10.728 ;
    END
  END rd_out[222]
  PIN rd_out[223]
    DIRECTION OUTPUT ;
    USE SIGNAL ;
    SHAPE ABUTMENT ;
    PORT
      LAYER M4 ;
      RECT 0.000 10.752 0.036 10.776 ;
    END
  END rd_out[223]
  PIN rd_out[224]
    DIRECTION OUTPUT ;
    USE SIGNAL ;
    SHAPE ABUTMENT ;
    PORT
      LAYER M4 ;
      RECT 0.000 10.800 0.036 10.824 ;
    END
  END rd_out[224]
  PIN rd_out[225]
    DIRECTION OUTPUT ;
    USE SIGNAL ;
    SHAPE ABUTMENT ;
    PORT
      LAYER M4 ;
      RECT 0.000 10.848 0.036 10.872 ;
    END
  END rd_out[225]
  PIN rd_out[226]
    DIRECTION OUTPUT ;
    USE SIGNAL ;
    SHAPE ABUTMENT ;
    PORT
      LAYER M4 ;
      RECT 0.000 10.896 0.036 10.920 ;
    END
  END rd_out[226]
  PIN rd_out[227]
    DIRECTION OUTPUT ;
    USE SIGNAL ;
    SHAPE ABUTMENT ;
    PORT
      LAYER M4 ;
      RECT 0.000 10.944 0.036 10.968 ;
    END
  END rd_out[227]
  PIN rd_out[228]
    DIRECTION OUTPUT ;
    USE SIGNAL ;
    SHAPE ABUTMENT ;
    PORT
      LAYER M4 ;
      RECT 0.000 10.992 0.036 11.016 ;
    END
  END rd_out[228]
  PIN rd_out[229]
    DIRECTION OUTPUT ;
    USE SIGNAL ;
    SHAPE ABUTMENT ;
    PORT
      LAYER M4 ;
      RECT 0.000 11.040 0.036 11.064 ;
    END
  END rd_out[229]
  PIN rd_out[230]
    DIRECTION OUTPUT ;
    USE SIGNAL ;
    SHAPE ABUTMENT ;
    PORT
      LAYER M4 ;
      RECT 0.000 11.088 0.036 11.112 ;
    END
  END rd_out[230]
  PIN rd_out[231]
    DIRECTION OUTPUT ;
    USE SIGNAL ;
    SHAPE ABUTMENT ;
    PORT
      LAYER M4 ;
      RECT 0.000 11.136 0.036 11.160 ;
    END
  END rd_out[231]
  PIN rd_out[232]
    DIRECTION OUTPUT ;
    USE SIGNAL ;
    SHAPE ABUTMENT ;
    PORT
      LAYER M4 ;
      RECT 0.000 11.184 0.036 11.208 ;
    END
  END rd_out[232]
  PIN rd_out[233]
    DIRECTION OUTPUT ;
    USE SIGNAL ;
    SHAPE ABUTMENT ;
    PORT
      LAYER M4 ;
      RECT 0.000 11.232 0.036 11.256 ;
    END
  END rd_out[233]
  PIN rd_out[234]
    DIRECTION OUTPUT ;
    USE SIGNAL ;
    SHAPE ABUTMENT ;
    PORT
      LAYER M4 ;
      RECT 0.000 11.280 0.036 11.304 ;
    END
  END rd_out[234]
  PIN rd_out[235]
    DIRECTION OUTPUT ;
    USE SIGNAL ;
    SHAPE ABUTMENT ;
    PORT
      LAYER M4 ;
      RECT 0.000 11.328 0.036 11.352 ;
    END
  END rd_out[235]
  PIN rd_out[236]
    DIRECTION OUTPUT ;
    USE SIGNAL ;
    SHAPE ABUTMENT ;
    PORT
      LAYER M4 ;
      RECT 0.000 11.376 0.036 11.400 ;
    END
  END rd_out[236]
  PIN rd_out[237]
    DIRECTION OUTPUT ;
    USE SIGNAL ;
    SHAPE ABUTMENT ;
    PORT
      LAYER M4 ;
      RECT 0.000 11.424 0.036 11.448 ;
    END
  END rd_out[237]
  PIN rd_out[238]
    DIRECTION OUTPUT ;
    USE SIGNAL ;
    SHAPE ABUTMENT ;
    PORT
      LAYER M4 ;
      RECT 0.000 11.472 0.036 11.496 ;
    END
  END rd_out[238]
  PIN rd_out[239]
    DIRECTION OUTPUT ;
    USE SIGNAL ;
    SHAPE ABUTMENT ;
    PORT
      LAYER M4 ;
      RECT 0.000 11.520 0.036 11.544 ;
    END
  END rd_out[239]
  PIN rd_out[240]
    DIRECTION OUTPUT ;
    USE SIGNAL ;
    SHAPE ABUTMENT ;
    PORT
      LAYER M4 ;
      RECT 0.000 11.568 0.036 11.592 ;
    END
  END rd_out[240]
  PIN rd_out[241]
    DIRECTION OUTPUT ;
    USE SIGNAL ;
    SHAPE ABUTMENT ;
    PORT
      LAYER M4 ;
      RECT 0.000 11.616 0.036 11.640 ;
    END
  END rd_out[241]
  PIN rd_out[242]
    DIRECTION OUTPUT ;
    USE SIGNAL ;
    SHAPE ABUTMENT ;
    PORT
      LAYER M4 ;
      RECT 0.000 11.664 0.036 11.688 ;
    END
  END rd_out[242]
  PIN rd_out[243]
    DIRECTION OUTPUT ;
    USE SIGNAL ;
    SHAPE ABUTMENT ;
    PORT
      LAYER M4 ;
      RECT 0.000 11.712 0.036 11.736 ;
    END
  END rd_out[243]
  PIN rd_out[244]
    DIRECTION OUTPUT ;
    USE SIGNAL ;
    SHAPE ABUTMENT ;
    PORT
      LAYER M4 ;
      RECT 0.000 11.760 0.036 11.784 ;
    END
  END rd_out[244]
  PIN rd_out[245]
    DIRECTION OUTPUT ;
    USE SIGNAL ;
    SHAPE ABUTMENT ;
    PORT
      LAYER M4 ;
      RECT 0.000 11.808 0.036 11.832 ;
    END
  END rd_out[245]
  PIN rd_out[246]
    DIRECTION OUTPUT ;
    USE SIGNAL ;
    SHAPE ABUTMENT ;
    PORT
      LAYER M4 ;
      RECT 0.000 11.856 0.036 11.880 ;
    END
  END rd_out[246]
  PIN rd_out[247]
    DIRECTION OUTPUT ;
    USE SIGNAL ;
    SHAPE ABUTMENT ;
    PORT
      LAYER M4 ;
      RECT 0.000 11.904 0.036 11.928 ;
    END
  END rd_out[247]
  PIN rd_out[248]
    DIRECTION OUTPUT ;
    USE SIGNAL ;
    SHAPE ABUTMENT ;
    PORT
      LAYER M4 ;
      RECT 0.000 11.952 0.036 11.976 ;
    END
  END rd_out[248]
  PIN rd_out[249]
    DIRECTION OUTPUT ;
    USE SIGNAL ;
    SHAPE ABUTMENT ;
    PORT
      LAYER M4 ;
      RECT 0.000 12.000 0.036 12.024 ;
    END
  END rd_out[249]
  PIN rd_out[250]
    DIRECTION OUTPUT ;
    USE SIGNAL ;
    SHAPE ABUTMENT ;
    PORT
      LAYER M4 ;
      RECT 0.000 12.048 0.036 12.072 ;
    END
  END rd_out[250]
  PIN rd_out[251]
    DIRECTION OUTPUT ;
    USE SIGNAL ;
    SHAPE ABUTMENT ;
    PORT
      LAYER M4 ;
      RECT 0.000 12.096 0.036 12.120 ;
    END
  END rd_out[251]
  PIN rd_out[252]
    DIRECTION OUTPUT ;
    USE SIGNAL ;
    SHAPE ABUTMENT ;
    PORT
      LAYER M4 ;
      RECT 0.000 12.144 0.036 12.168 ;
    END
  END rd_out[252]
  PIN rd_out[253]
    DIRECTION OUTPUT ;
    USE SIGNAL ;
    SHAPE ABUTMENT ;
    PORT
      LAYER M4 ;
      RECT 0.000 12.192 0.036 12.216 ;
    END
  END rd_out[253]
  PIN rd_out[254]
    DIRECTION OUTPUT ;
    USE SIGNAL ;
    SHAPE ABUTMENT ;
    PORT
      LAYER M4 ;
      RECT 0.000 12.240 0.036 12.264 ;
    END
  END rd_out[254]
  PIN rd_out[255]
    DIRECTION OUTPUT ;
    USE SIGNAL ;
    SHAPE ABUTMENT ;
    PORT
      LAYER M4 ;
      RECT 0.000 12.288 0.036 12.312 ;
    END
  END rd_out[255]
  PIN wd_in[0]
    DIRECTION INPUT ;
    USE SIGNAL ;
    SHAPE ABUTMENT ;
    PORT
      LAYER M4 ;
      RECT 0.000 19.536 0.036 19.560 ;
    END
  END wd_in[0]
  PIN wd_in[1]
    DIRECTION INPUT ;
    USE SIGNAL ;
    SHAPE ABUTMENT ;
    PORT
      LAYER M4 ;
      RECT 0.000 19.584 0.036 19.608 ;
    END
  END wd_in[1]
  PIN wd_in[2]
    DIRECTION INPUT ;
    USE SIGNAL ;
    SHAPE ABUTMENT ;
    PORT
      LAYER M4 ;
      RECT 0.000 19.632 0.036 19.656 ;
    END
  END wd_in[2]
  PIN wd_in[3]
    DIRECTION INPUT ;
    USE SIGNAL ;
    SHAPE ABUTMENT ;
    PORT
      LAYER M4 ;
      RECT 0.000 19.680 0.036 19.704 ;
    END
  END wd_in[3]
  PIN wd_in[4]
    DIRECTION INPUT ;
    USE SIGNAL ;
    SHAPE ABUTMENT ;
    PORT
      LAYER M4 ;
      RECT 0.000 19.728 0.036 19.752 ;
    END
  END wd_in[4]
  PIN wd_in[5]
    DIRECTION INPUT ;
    USE SIGNAL ;
    SHAPE ABUTMENT ;
    PORT
      LAYER M4 ;
      RECT 0.000 19.776 0.036 19.800 ;
    END
  END wd_in[5]
  PIN wd_in[6]
    DIRECTION INPUT ;
    USE SIGNAL ;
    SHAPE ABUTMENT ;
    PORT
      LAYER M4 ;
      RECT 0.000 19.824 0.036 19.848 ;
    END
  END wd_in[6]
  PIN wd_in[7]
    DIRECTION INPUT ;
    USE SIGNAL ;
    SHAPE ABUTMENT ;
    PORT
      LAYER M4 ;
      RECT 0.000 19.872 0.036 19.896 ;
    END
  END wd_in[7]
  PIN wd_in[8]
    DIRECTION INPUT ;
    USE SIGNAL ;
    SHAPE ABUTMENT ;
    PORT
      LAYER M4 ;
      RECT 0.000 19.920 0.036 19.944 ;
    END
  END wd_in[8]
  PIN wd_in[9]
    DIRECTION INPUT ;
    USE SIGNAL ;
    SHAPE ABUTMENT ;
    PORT
      LAYER M4 ;
      RECT 0.000 19.968 0.036 19.992 ;
    END
  END wd_in[9]
  PIN wd_in[10]
    DIRECTION INPUT ;
    USE SIGNAL ;
    SHAPE ABUTMENT ;
    PORT
      LAYER M4 ;
      RECT 0.000 20.016 0.036 20.040 ;
    END
  END wd_in[10]
  PIN wd_in[11]
    DIRECTION INPUT ;
    USE SIGNAL ;
    SHAPE ABUTMENT ;
    PORT
      LAYER M4 ;
      RECT 0.000 20.064 0.036 20.088 ;
    END
  END wd_in[11]
  PIN wd_in[12]
    DIRECTION INPUT ;
    USE SIGNAL ;
    SHAPE ABUTMENT ;
    PORT
      LAYER M4 ;
      RECT 0.000 20.112 0.036 20.136 ;
    END
  END wd_in[12]
  PIN wd_in[13]
    DIRECTION INPUT ;
    USE SIGNAL ;
    SHAPE ABUTMENT ;
    PORT
      LAYER M4 ;
      RECT 0.000 20.160 0.036 20.184 ;
    END
  END wd_in[13]
  PIN wd_in[14]
    DIRECTION INPUT ;
    USE SIGNAL ;
    SHAPE ABUTMENT ;
    PORT
      LAYER M4 ;
      RECT 0.000 20.208 0.036 20.232 ;
    END
  END wd_in[14]
  PIN wd_in[15]
    DIRECTION INPUT ;
    USE SIGNAL ;
    SHAPE ABUTMENT ;
    PORT
      LAYER M4 ;
      RECT 0.000 20.256 0.036 20.280 ;
    END
  END wd_in[15]
  PIN wd_in[16]
    DIRECTION INPUT ;
    USE SIGNAL ;
    SHAPE ABUTMENT ;
    PORT
      LAYER M4 ;
      RECT 0.000 20.304 0.036 20.328 ;
    END
  END wd_in[16]
  PIN wd_in[17]
    DIRECTION INPUT ;
    USE SIGNAL ;
    SHAPE ABUTMENT ;
    PORT
      LAYER M4 ;
      RECT 0.000 20.352 0.036 20.376 ;
    END
  END wd_in[17]
  PIN wd_in[18]
    DIRECTION INPUT ;
    USE SIGNAL ;
    SHAPE ABUTMENT ;
    PORT
      LAYER M4 ;
      RECT 0.000 20.400 0.036 20.424 ;
    END
  END wd_in[18]
  PIN wd_in[19]
    DIRECTION INPUT ;
    USE SIGNAL ;
    SHAPE ABUTMENT ;
    PORT
      LAYER M4 ;
      RECT 0.000 20.448 0.036 20.472 ;
    END
  END wd_in[19]
  PIN wd_in[20]
    DIRECTION INPUT ;
    USE SIGNAL ;
    SHAPE ABUTMENT ;
    PORT
      LAYER M4 ;
      RECT 0.000 20.496 0.036 20.520 ;
    END
  END wd_in[20]
  PIN wd_in[21]
    DIRECTION INPUT ;
    USE SIGNAL ;
    SHAPE ABUTMENT ;
    PORT
      LAYER M4 ;
      RECT 0.000 20.544 0.036 20.568 ;
    END
  END wd_in[21]
  PIN wd_in[22]
    DIRECTION INPUT ;
    USE SIGNAL ;
    SHAPE ABUTMENT ;
    PORT
      LAYER M4 ;
      RECT 0.000 20.592 0.036 20.616 ;
    END
  END wd_in[22]
  PIN wd_in[23]
    DIRECTION INPUT ;
    USE SIGNAL ;
    SHAPE ABUTMENT ;
    PORT
      LAYER M4 ;
      RECT 0.000 20.640 0.036 20.664 ;
    END
  END wd_in[23]
  PIN wd_in[24]
    DIRECTION INPUT ;
    USE SIGNAL ;
    SHAPE ABUTMENT ;
    PORT
      LAYER M4 ;
      RECT 0.000 20.688 0.036 20.712 ;
    END
  END wd_in[24]
  PIN wd_in[25]
    DIRECTION INPUT ;
    USE SIGNAL ;
    SHAPE ABUTMENT ;
    PORT
      LAYER M4 ;
      RECT 0.000 20.736 0.036 20.760 ;
    END
  END wd_in[25]
  PIN wd_in[26]
    DIRECTION INPUT ;
    USE SIGNAL ;
    SHAPE ABUTMENT ;
    PORT
      LAYER M4 ;
      RECT 0.000 20.784 0.036 20.808 ;
    END
  END wd_in[26]
  PIN wd_in[27]
    DIRECTION INPUT ;
    USE SIGNAL ;
    SHAPE ABUTMENT ;
    PORT
      LAYER M4 ;
      RECT 0.000 20.832 0.036 20.856 ;
    END
  END wd_in[27]
  PIN wd_in[28]
    DIRECTION INPUT ;
    USE SIGNAL ;
    SHAPE ABUTMENT ;
    PORT
      LAYER M4 ;
      RECT 0.000 20.880 0.036 20.904 ;
    END
  END wd_in[28]
  PIN wd_in[29]
    DIRECTION INPUT ;
    USE SIGNAL ;
    SHAPE ABUTMENT ;
    PORT
      LAYER M4 ;
      RECT 0.000 20.928 0.036 20.952 ;
    END
  END wd_in[29]
  PIN wd_in[30]
    DIRECTION INPUT ;
    USE SIGNAL ;
    SHAPE ABUTMENT ;
    PORT
      LAYER M4 ;
      RECT 0.000 20.976 0.036 21.000 ;
    END
  END wd_in[30]
  PIN wd_in[31]
    DIRECTION INPUT ;
    USE SIGNAL ;
    SHAPE ABUTMENT ;
    PORT
      LAYER M4 ;
      RECT 0.000 21.024 0.036 21.048 ;
    END
  END wd_in[31]
  PIN wd_in[32]
    DIRECTION INPUT ;
    USE SIGNAL ;
    SHAPE ABUTMENT ;
    PORT
      LAYER M4 ;
      RECT 0.000 21.072 0.036 21.096 ;
    END
  END wd_in[32]
  PIN wd_in[33]
    DIRECTION INPUT ;
    USE SIGNAL ;
    SHAPE ABUTMENT ;
    PORT
      LAYER M4 ;
      RECT 0.000 21.120 0.036 21.144 ;
    END
  END wd_in[33]
  PIN wd_in[34]
    DIRECTION INPUT ;
    USE SIGNAL ;
    SHAPE ABUTMENT ;
    PORT
      LAYER M4 ;
      RECT 0.000 21.168 0.036 21.192 ;
    END
  END wd_in[34]
  PIN wd_in[35]
    DIRECTION INPUT ;
    USE SIGNAL ;
    SHAPE ABUTMENT ;
    PORT
      LAYER M4 ;
      RECT 0.000 21.216 0.036 21.240 ;
    END
  END wd_in[35]
  PIN wd_in[36]
    DIRECTION INPUT ;
    USE SIGNAL ;
    SHAPE ABUTMENT ;
    PORT
      LAYER M4 ;
      RECT 0.000 21.264 0.036 21.288 ;
    END
  END wd_in[36]
  PIN wd_in[37]
    DIRECTION INPUT ;
    USE SIGNAL ;
    SHAPE ABUTMENT ;
    PORT
      LAYER M4 ;
      RECT 0.000 21.312 0.036 21.336 ;
    END
  END wd_in[37]
  PIN wd_in[38]
    DIRECTION INPUT ;
    USE SIGNAL ;
    SHAPE ABUTMENT ;
    PORT
      LAYER M4 ;
      RECT 0.000 21.360 0.036 21.384 ;
    END
  END wd_in[38]
  PIN wd_in[39]
    DIRECTION INPUT ;
    USE SIGNAL ;
    SHAPE ABUTMENT ;
    PORT
      LAYER M4 ;
      RECT 0.000 21.408 0.036 21.432 ;
    END
  END wd_in[39]
  PIN wd_in[40]
    DIRECTION INPUT ;
    USE SIGNAL ;
    SHAPE ABUTMENT ;
    PORT
      LAYER M4 ;
      RECT 0.000 21.456 0.036 21.480 ;
    END
  END wd_in[40]
  PIN wd_in[41]
    DIRECTION INPUT ;
    USE SIGNAL ;
    SHAPE ABUTMENT ;
    PORT
      LAYER M4 ;
      RECT 0.000 21.504 0.036 21.528 ;
    END
  END wd_in[41]
  PIN wd_in[42]
    DIRECTION INPUT ;
    USE SIGNAL ;
    SHAPE ABUTMENT ;
    PORT
      LAYER M4 ;
      RECT 0.000 21.552 0.036 21.576 ;
    END
  END wd_in[42]
  PIN wd_in[43]
    DIRECTION INPUT ;
    USE SIGNAL ;
    SHAPE ABUTMENT ;
    PORT
      LAYER M4 ;
      RECT 0.000 21.600 0.036 21.624 ;
    END
  END wd_in[43]
  PIN wd_in[44]
    DIRECTION INPUT ;
    USE SIGNAL ;
    SHAPE ABUTMENT ;
    PORT
      LAYER M4 ;
      RECT 0.000 21.648 0.036 21.672 ;
    END
  END wd_in[44]
  PIN wd_in[45]
    DIRECTION INPUT ;
    USE SIGNAL ;
    SHAPE ABUTMENT ;
    PORT
      LAYER M4 ;
      RECT 0.000 21.696 0.036 21.720 ;
    END
  END wd_in[45]
  PIN wd_in[46]
    DIRECTION INPUT ;
    USE SIGNAL ;
    SHAPE ABUTMENT ;
    PORT
      LAYER M4 ;
      RECT 0.000 21.744 0.036 21.768 ;
    END
  END wd_in[46]
  PIN wd_in[47]
    DIRECTION INPUT ;
    USE SIGNAL ;
    SHAPE ABUTMENT ;
    PORT
      LAYER M4 ;
      RECT 0.000 21.792 0.036 21.816 ;
    END
  END wd_in[47]
  PIN wd_in[48]
    DIRECTION INPUT ;
    USE SIGNAL ;
    SHAPE ABUTMENT ;
    PORT
      LAYER M4 ;
      RECT 0.000 21.840 0.036 21.864 ;
    END
  END wd_in[48]
  PIN wd_in[49]
    DIRECTION INPUT ;
    USE SIGNAL ;
    SHAPE ABUTMENT ;
    PORT
      LAYER M4 ;
      RECT 0.000 21.888 0.036 21.912 ;
    END
  END wd_in[49]
  PIN wd_in[50]
    DIRECTION INPUT ;
    USE SIGNAL ;
    SHAPE ABUTMENT ;
    PORT
      LAYER M4 ;
      RECT 0.000 21.936 0.036 21.960 ;
    END
  END wd_in[50]
  PIN wd_in[51]
    DIRECTION INPUT ;
    USE SIGNAL ;
    SHAPE ABUTMENT ;
    PORT
      LAYER M4 ;
      RECT 0.000 21.984 0.036 22.008 ;
    END
  END wd_in[51]
  PIN wd_in[52]
    DIRECTION INPUT ;
    USE SIGNAL ;
    SHAPE ABUTMENT ;
    PORT
      LAYER M4 ;
      RECT 0.000 22.032 0.036 22.056 ;
    END
  END wd_in[52]
  PIN wd_in[53]
    DIRECTION INPUT ;
    USE SIGNAL ;
    SHAPE ABUTMENT ;
    PORT
      LAYER M4 ;
      RECT 0.000 22.080 0.036 22.104 ;
    END
  END wd_in[53]
  PIN wd_in[54]
    DIRECTION INPUT ;
    USE SIGNAL ;
    SHAPE ABUTMENT ;
    PORT
      LAYER M4 ;
      RECT 0.000 22.128 0.036 22.152 ;
    END
  END wd_in[54]
  PIN wd_in[55]
    DIRECTION INPUT ;
    USE SIGNAL ;
    SHAPE ABUTMENT ;
    PORT
      LAYER M4 ;
      RECT 0.000 22.176 0.036 22.200 ;
    END
  END wd_in[55]
  PIN wd_in[56]
    DIRECTION INPUT ;
    USE SIGNAL ;
    SHAPE ABUTMENT ;
    PORT
      LAYER M4 ;
      RECT 0.000 22.224 0.036 22.248 ;
    END
  END wd_in[56]
  PIN wd_in[57]
    DIRECTION INPUT ;
    USE SIGNAL ;
    SHAPE ABUTMENT ;
    PORT
      LAYER M4 ;
      RECT 0.000 22.272 0.036 22.296 ;
    END
  END wd_in[57]
  PIN wd_in[58]
    DIRECTION INPUT ;
    USE SIGNAL ;
    SHAPE ABUTMENT ;
    PORT
      LAYER M4 ;
      RECT 0.000 22.320 0.036 22.344 ;
    END
  END wd_in[58]
  PIN wd_in[59]
    DIRECTION INPUT ;
    USE SIGNAL ;
    SHAPE ABUTMENT ;
    PORT
      LAYER M4 ;
      RECT 0.000 22.368 0.036 22.392 ;
    END
  END wd_in[59]
  PIN wd_in[60]
    DIRECTION INPUT ;
    USE SIGNAL ;
    SHAPE ABUTMENT ;
    PORT
      LAYER M4 ;
      RECT 0.000 22.416 0.036 22.440 ;
    END
  END wd_in[60]
  PIN wd_in[61]
    DIRECTION INPUT ;
    USE SIGNAL ;
    SHAPE ABUTMENT ;
    PORT
      LAYER M4 ;
      RECT 0.000 22.464 0.036 22.488 ;
    END
  END wd_in[61]
  PIN wd_in[62]
    DIRECTION INPUT ;
    USE SIGNAL ;
    SHAPE ABUTMENT ;
    PORT
      LAYER M4 ;
      RECT 0.000 22.512 0.036 22.536 ;
    END
  END wd_in[62]
  PIN wd_in[63]
    DIRECTION INPUT ;
    USE SIGNAL ;
    SHAPE ABUTMENT ;
    PORT
      LAYER M4 ;
      RECT 0.000 22.560 0.036 22.584 ;
    END
  END wd_in[63]
  PIN wd_in[64]
    DIRECTION INPUT ;
    USE SIGNAL ;
    SHAPE ABUTMENT ;
    PORT
      LAYER M4 ;
      RECT 0.000 22.608 0.036 22.632 ;
    END
  END wd_in[64]
  PIN wd_in[65]
    DIRECTION INPUT ;
    USE SIGNAL ;
    SHAPE ABUTMENT ;
    PORT
      LAYER M4 ;
      RECT 0.000 22.656 0.036 22.680 ;
    END
  END wd_in[65]
  PIN wd_in[66]
    DIRECTION INPUT ;
    USE SIGNAL ;
    SHAPE ABUTMENT ;
    PORT
      LAYER M4 ;
      RECT 0.000 22.704 0.036 22.728 ;
    END
  END wd_in[66]
  PIN wd_in[67]
    DIRECTION INPUT ;
    USE SIGNAL ;
    SHAPE ABUTMENT ;
    PORT
      LAYER M4 ;
      RECT 0.000 22.752 0.036 22.776 ;
    END
  END wd_in[67]
  PIN wd_in[68]
    DIRECTION INPUT ;
    USE SIGNAL ;
    SHAPE ABUTMENT ;
    PORT
      LAYER M4 ;
      RECT 0.000 22.800 0.036 22.824 ;
    END
  END wd_in[68]
  PIN wd_in[69]
    DIRECTION INPUT ;
    USE SIGNAL ;
    SHAPE ABUTMENT ;
    PORT
      LAYER M4 ;
      RECT 0.000 22.848 0.036 22.872 ;
    END
  END wd_in[69]
  PIN wd_in[70]
    DIRECTION INPUT ;
    USE SIGNAL ;
    SHAPE ABUTMENT ;
    PORT
      LAYER M4 ;
      RECT 0.000 22.896 0.036 22.920 ;
    END
  END wd_in[70]
  PIN wd_in[71]
    DIRECTION INPUT ;
    USE SIGNAL ;
    SHAPE ABUTMENT ;
    PORT
      LAYER M4 ;
      RECT 0.000 22.944 0.036 22.968 ;
    END
  END wd_in[71]
  PIN wd_in[72]
    DIRECTION INPUT ;
    USE SIGNAL ;
    SHAPE ABUTMENT ;
    PORT
      LAYER M4 ;
      RECT 0.000 22.992 0.036 23.016 ;
    END
  END wd_in[72]
  PIN wd_in[73]
    DIRECTION INPUT ;
    USE SIGNAL ;
    SHAPE ABUTMENT ;
    PORT
      LAYER M4 ;
      RECT 0.000 23.040 0.036 23.064 ;
    END
  END wd_in[73]
  PIN wd_in[74]
    DIRECTION INPUT ;
    USE SIGNAL ;
    SHAPE ABUTMENT ;
    PORT
      LAYER M4 ;
      RECT 0.000 23.088 0.036 23.112 ;
    END
  END wd_in[74]
  PIN wd_in[75]
    DIRECTION INPUT ;
    USE SIGNAL ;
    SHAPE ABUTMENT ;
    PORT
      LAYER M4 ;
      RECT 0.000 23.136 0.036 23.160 ;
    END
  END wd_in[75]
  PIN wd_in[76]
    DIRECTION INPUT ;
    USE SIGNAL ;
    SHAPE ABUTMENT ;
    PORT
      LAYER M4 ;
      RECT 0.000 23.184 0.036 23.208 ;
    END
  END wd_in[76]
  PIN wd_in[77]
    DIRECTION INPUT ;
    USE SIGNAL ;
    SHAPE ABUTMENT ;
    PORT
      LAYER M4 ;
      RECT 0.000 23.232 0.036 23.256 ;
    END
  END wd_in[77]
  PIN wd_in[78]
    DIRECTION INPUT ;
    USE SIGNAL ;
    SHAPE ABUTMENT ;
    PORT
      LAYER M4 ;
      RECT 0.000 23.280 0.036 23.304 ;
    END
  END wd_in[78]
  PIN wd_in[79]
    DIRECTION INPUT ;
    USE SIGNAL ;
    SHAPE ABUTMENT ;
    PORT
      LAYER M4 ;
      RECT 0.000 23.328 0.036 23.352 ;
    END
  END wd_in[79]
  PIN wd_in[80]
    DIRECTION INPUT ;
    USE SIGNAL ;
    SHAPE ABUTMENT ;
    PORT
      LAYER M4 ;
      RECT 0.000 23.376 0.036 23.400 ;
    END
  END wd_in[80]
  PIN wd_in[81]
    DIRECTION INPUT ;
    USE SIGNAL ;
    SHAPE ABUTMENT ;
    PORT
      LAYER M4 ;
      RECT 0.000 23.424 0.036 23.448 ;
    END
  END wd_in[81]
  PIN wd_in[82]
    DIRECTION INPUT ;
    USE SIGNAL ;
    SHAPE ABUTMENT ;
    PORT
      LAYER M4 ;
      RECT 0.000 23.472 0.036 23.496 ;
    END
  END wd_in[82]
  PIN wd_in[83]
    DIRECTION INPUT ;
    USE SIGNAL ;
    SHAPE ABUTMENT ;
    PORT
      LAYER M4 ;
      RECT 0.000 23.520 0.036 23.544 ;
    END
  END wd_in[83]
  PIN wd_in[84]
    DIRECTION INPUT ;
    USE SIGNAL ;
    SHAPE ABUTMENT ;
    PORT
      LAYER M4 ;
      RECT 0.000 23.568 0.036 23.592 ;
    END
  END wd_in[84]
  PIN wd_in[85]
    DIRECTION INPUT ;
    USE SIGNAL ;
    SHAPE ABUTMENT ;
    PORT
      LAYER M4 ;
      RECT 0.000 23.616 0.036 23.640 ;
    END
  END wd_in[85]
  PIN wd_in[86]
    DIRECTION INPUT ;
    USE SIGNAL ;
    SHAPE ABUTMENT ;
    PORT
      LAYER M4 ;
      RECT 0.000 23.664 0.036 23.688 ;
    END
  END wd_in[86]
  PIN wd_in[87]
    DIRECTION INPUT ;
    USE SIGNAL ;
    SHAPE ABUTMENT ;
    PORT
      LAYER M4 ;
      RECT 0.000 23.712 0.036 23.736 ;
    END
  END wd_in[87]
  PIN wd_in[88]
    DIRECTION INPUT ;
    USE SIGNAL ;
    SHAPE ABUTMENT ;
    PORT
      LAYER M4 ;
      RECT 0.000 23.760 0.036 23.784 ;
    END
  END wd_in[88]
  PIN wd_in[89]
    DIRECTION INPUT ;
    USE SIGNAL ;
    SHAPE ABUTMENT ;
    PORT
      LAYER M4 ;
      RECT 0.000 23.808 0.036 23.832 ;
    END
  END wd_in[89]
  PIN wd_in[90]
    DIRECTION INPUT ;
    USE SIGNAL ;
    SHAPE ABUTMENT ;
    PORT
      LAYER M4 ;
      RECT 0.000 23.856 0.036 23.880 ;
    END
  END wd_in[90]
  PIN wd_in[91]
    DIRECTION INPUT ;
    USE SIGNAL ;
    SHAPE ABUTMENT ;
    PORT
      LAYER M4 ;
      RECT 0.000 23.904 0.036 23.928 ;
    END
  END wd_in[91]
  PIN wd_in[92]
    DIRECTION INPUT ;
    USE SIGNAL ;
    SHAPE ABUTMENT ;
    PORT
      LAYER M4 ;
      RECT 0.000 23.952 0.036 23.976 ;
    END
  END wd_in[92]
  PIN wd_in[93]
    DIRECTION INPUT ;
    USE SIGNAL ;
    SHAPE ABUTMENT ;
    PORT
      LAYER M4 ;
      RECT 0.000 24.000 0.036 24.024 ;
    END
  END wd_in[93]
  PIN wd_in[94]
    DIRECTION INPUT ;
    USE SIGNAL ;
    SHAPE ABUTMENT ;
    PORT
      LAYER M4 ;
      RECT 0.000 24.048 0.036 24.072 ;
    END
  END wd_in[94]
  PIN wd_in[95]
    DIRECTION INPUT ;
    USE SIGNAL ;
    SHAPE ABUTMENT ;
    PORT
      LAYER M4 ;
      RECT 0.000 24.096 0.036 24.120 ;
    END
  END wd_in[95]
  PIN wd_in[96]
    DIRECTION INPUT ;
    USE SIGNAL ;
    SHAPE ABUTMENT ;
    PORT
      LAYER M4 ;
      RECT 0.000 24.144 0.036 24.168 ;
    END
  END wd_in[96]
  PIN wd_in[97]
    DIRECTION INPUT ;
    USE SIGNAL ;
    SHAPE ABUTMENT ;
    PORT
      LAYER M4 ;
      RECT 0.000 24.192 0.036 24.216 ;
    END
  END wd_in[97]
  PIN wd_in[98]
    DIRECTION INPUT ;
    USE SIGNAL ;
    SHAPE ABUTMENT ;
    PORT
      LAYER M4 ;
      RECT 0.000 24.240 0.036 24.264 ;
    END
  END wd_in[98]
  PIN wd_in[99]
    DIRECTION INPUT ;
    USE SIGNAL ;
    SHAPE ABUTMENT ;
    PORT
      LAYER M4 ;
      RECT 0.000 24.288 0.036 24.312 ;
    END
  END wd_in[99]
  PIN wd_in[100]
    DIRECTION INPUT ;
    USE SIGNAL ;
    SHAPE ABUTMENT ;
    PORT
      LAYER M4 ;
      RECT 0.000 24.336 0.036 24.360 ;
    END
  END wd_in[100]
  PIN wd_in[101]
    DIRECTION INPUT ;
    USE SIGNAL ;
    SHAPE ABUTMENT ;
    PORT
      LAYER M4 ;
      RECT 0.000 24.384 0.036 24.408 ;
    END
  END wd_in[101]
  PIN wd_in[102]
    DIRECTION INPUT ;
    USE SIGNAL ;
    SHAPE ABUTMENT ;
    PORT
      LAYER M4 ;
      RECT 0.000 24.432 0.036 24.456 ;
    END
  END wd_in[102]
  PIN wd_in[103]
    DIRECTION INPUT ;
    USE SIGNAL ;
    SHAPE ABUTMENT ;
    PORT
      LAYER M4 ;
      RECT 0.000 24.480 0.036 24.504 ;
    END
  END wd_in[103]
  PIN wd_in[104]
    DIRECTION INPUT ;
    USE SIGNAL ;
    SHAPE ABUTMENT ;
    PORT
      LAYER M4 ;
      RECT 0.000 24.528 0.036 24.552 ;
    END
  END wd_in[104]
  PIN wd_in[105]
    DIRECTION INPUT ;
    USE SIGNAL ;
    SHAPE ABUTMENT ;
    PORT
      LAYER M4 ;
      RECT 0.000 24.576 0.036 24.600 ;
    END
  END wd_in[105]
  PIN wd_in[106]
    DIRECTION INPUT ;
    USE SIGNAL ;
    SHAPE ABUTMENT ;
    PORT
      LAYER M4 ;
      RECT 0.000 24.624 0.036 24.648 ;
    END
  END wd_in[106]
  PIN wd_in[107]
    DIRECTION INPUT ;
    USE SIGNAL ;
    SHAPE ABUTMENT ;
    PORT
      LAYER M4 ;
      RECT 0.000 24.672 0.036 24.696 ;
    END
  END wd_in[107]
  PIN wd_in[108]
    DIRECTION INPUT ;
    USE SIGNAL ;
    SHAPE ABUTMENT ;
    PORT
      LAYER M4 ;
      RECT 0.000 24.720 0.036 24.744 ;
    END
  END wd_in[108]
  PIN wd_in[109]
    DIRECTION INPUT ;
    USE SIGNAL ;
    SHAPE ABUTMENT ;
    PORT
      LAYER M4 ;
      RECT 0.000 24.768 0.036 24.792 ;
    END
  END wd_in[109]
  PIN wd_in[110]
    DIRECTION INPUT ;
    USE SIGNAL ;
    SHAPE ABUTMENT ;
    PORT
      LAYER M4 ;
      RECT 0.000 24.816 0.036 24.840 ;
    END
  END wd_in[110]
  PIN wd_in[111]
    DIRECTION INPUT ;
    USE SIGNAL ;
    SHAPE ABUTMENT ;
    PORT
      LAYER M4 ;
      RECT 0.000 24.864 0.036 24.888 ;
    END
  END wd_in[111]
  PIN wd_in[112]
    DIRECTION INPUT ;
    USE SIGNAL ;
    SHAPE ABUTMENT ;
    PORT
      LAYER M4 ;
      RECT 0.000 24.912 0.036 24.936 ;
    END
  END wd_in[112]
  PIN wd_in[113]
    DIRECTION INPUT ;
    USE SIGNAL ;
    SHAPE ABUTMENT ;
    PORT
      LAYER M4 ;
      RECT 0.000 24.960 0.036 24.984 ;
    END
  END wd_in[113]
  PIN wd_in[114]
    DIRECTION INPUT ;
    USE SIGNAL ;
    SHAPE ABUTMENT ;
    PORT
      LAYER M4 ;
      RECT 0.000 25.008 0.036 25.032 ;
    END
  END wd_in[114]
  PIN wd_in[115]
    DIRECTION INPUT ;
    USE SIGNAL ;
    SHAPE ABUTMENT ;
    PORT
      LAYER M4 ;
      RECT 0.000 25.056 0.036 25.080 ;
    END
  END wd_in[115]
  PIN wd_in[116]
    DIRECTION INPUT ;
    USE SIGNAL ;
    SHAPE ABUTMENT ;
    PORT
      LAYER M4 ;
      RECT 0.000 25.104 0.036 25.128 ;
    END
  END wd_in[116]
  PIN wd_in[117]
    DIRECTION INPUT ;
    USE SIGNAL ;
    SHAPE ABUTMENT ;
    PORT
      LAYER M4 ;
      RECT 0.000 25.152 0.036 25.176 ;
    END
  END wd_in[117]
  PIN wd_in[118]
    DIRECTION INPUT ;
    USE SIGNAL ;
    SHAPE ABUTMENT ;
    PORT
      LAYER M4 ;
      RECT 0.000 25.200 0.036 25.224 ;
    END
  END wd_in[118]
  PIN wd_in[119]
    DIRECTION INPUT ;
    USE SIGNAL ;
    SHAPE ABUTMENT ;
    PORT
      LAYER M4 ;
      RECT 0.000 25.248 0.036 25.272 ;
    END
  END wd_in[119]
  PIN wd_in[120]
    DIRECTION INPUT ;
    USE SIGNAL ;
    SHAPE ABUTMENT ;
    PORT
      LAYER M4 ;
      RECT 0.000 25.296 0.036 25.320 ;
    END
  END wd_in[120]
  PIN wd_in[121]
    DIRECTION INPUT ;
    USE SIGNAL ;
    SHAPE ABUTMENT ;
    PORT
      LAYER M4 ;
      RECT 0.000 25.344 0.036 25.368 ;
    END
  END wd_in[121]
  PIN wd_in[122]
    DIRECTION INPUT ;
    USE SIGNAL ;
    SHAPE ABUTMENT ;
    PORT
      LAYER M4 ;
      RECT 0.000 25.392 0.036 25.416 ;
    END
  END wd_in[122]
  PIN wd_in[123]
    DIRECTION INPUT ;
    USE SIGNAL ;
    SHAPE ABUTMENT ;
    PORT
      LAYER M4 ;
      RECT 0.000 25.440 0.036 25.464 ;
    END
  END wd_in[123]
  PIN wd_in[124]
    DIRECTION INPUT ;
    USE SIGNAL ;
    SHAPE ABUTMENT ;
    PORT
      LAYER M4 ;
      RECT 0.000 25.488 0.036 25.512 ;
    END
  END wd_in[124]
  PIN wd_in[125]
    DIRECTION INPUT ;
    USE SIGNAL ;
    SHAPE ABUTMENT ;
    PORT
      LAYER M4 ;
      RECT 0.000 25.536 0.036 25.560 ;
    END
  END wd_in[125]
  PIN wd_in[126]
    DIRECTION INPUT ;
    USE SIGNAL ;
    SHAPE ABUTMENT ;
    PORT
      LAYER M4 ;
      RECT 0.000 25.584 0.036 25.608 ;
    END
  END wd_in[126]
  PIN wd_in[127]
    DIRECTION INPUT ;
    USE SIGNAL ;
    SHAPE ABUTMENT ;
    PORT
      LAYER M4 ;
      RECT 0.000 25.632 0.036 25.656 ;
    END
  END wd_in[127]
  PIN wd_in[128]
    DIRECTION INPUT ;
    USE SIGNAL ;
    SHAPE ABUTMENT ;
    PORT
      LAYER M4 ;
      RECT 0.000 25.680 0.036 25.704 ;
    END
  END wd_in[128]
  PIN wd_in[129]
    DIRECTION INPUT ;
    USE SIGNAL ;
    SHAPE ABUTMENT ;
    PORT
      LAYER M4 ;
      RECT 0.000 25.728 0.036 25.752 ;
    END
  END wd_in[129]
  PIN wd_in[130]
    DIRECTION INPUT ;
    USE SIGNAL ;
    SHAPE ABUTMENT ;
    PORT
      LAYER M4 ;
      RECT 0.000 25.776 0.036 25.800 ;
    END
  END wd_in[130]
  PIN wd_in[131]
    DIRECTION INPUT ;
    USE SIGNAL ;
    SHAPE ABUTMENT ;
    PORT
      LAYER M4 ;
      RECT 0.000 25.824 0.036 25.848 ;
    END
  END wd_in[131]
  PIN wd_in[132]
    DIRECTION INPUT ;
    USE SIGNAL ;
    SHAPE ABUTMENT ;
    PORT
      LAYER M4 ;
      RECT 0.000 25.872 0.036 25.896 ;
    END
  END wd_in[132]
  PIN wd_in[133]
    DIRECTION INPUT ;
    USE SIGNAL ;
    SHAPE ABUTMENT ;
    PORT
      LAYER M4 ;
      RECT 0.000 25.920 0.036 25.944 ;
    END
  END wd_in[133]
  PIN wd_in[134]
    DIRECTION INPUT ;
    USE SIGNAL ;
    SHAPE ABUTMENT ;
    PORT
      LAYER M4 ;
      RECT 0.000 25.968 0.036 25.992 ;
    END
  END wd_in[134]
  PIN wd_in[135]
    DIRECTION INPUT ;
    USE SIGNAL ;
    SHAPE ABUTMENT ;
    PORT
      LAYER M4 ;
      RECT 0.000 26.016 0.036 26.040 ;
    END
  END wd_in[135]
  PIN wd_in[136]
    DIRECTION INPUT ;
    USE SIGNAL ;
    SHAPE ABUTMENT ;
    PORT
      LAYER M4 ;
      RECT 0.000 26.064 0.036 26.088 ;
    END
  END wd_in[136]
  PIN wd_in[137]
    DIRECTION INPUT ;
    USE SIGNAL ;
    SHAPE ABUTMENT ;
    PORT
      LAYER M4 ;
      RECT 0.000 26.112 0.036 26.136 ;
    END
  END wd_in[137]
  PIN wd_in[138]
    DIRECTION INPUT ;
    USE SIGNAL ;
    SHAPE ABUTMENT ;
    PORT
      LAYER M4 ;
      RECT 0.000 26.160 0.036 26.184 ;
    END
  END wd_in[138]
  PIN wd_in[139]
    DIRECTION INPUT ;
    USE SIGNAL ;
    SHAPE ABUTMENT ;
    PORT
      LAYER M4 ;
      RECT 0.000 26.208 0.036 26.232 ;
    END
  END wd_in[139]
  PIN wd_in[140]
    DIRECTION INPUT ;
    USE SIGNAL ;
    SHAPE ABUTMENT ;
    PORT
      LAYER M4 ;
      RECT 0.000 26.256 0.036 26.280 ;
    END
  END wd_in[140]
  PIN wd_in[141]
    DIRECTION INPUT ;
    USE SIGNAL ;
    SHAPE ABUTMENT ;
    PORT
      LAYER M4 ;
      RECT 0.000 26.304 0.036 26.328 ;
    END
  END wd_in[141]
  PIN wd_in[142]
    DIRECTION INPUT ;
    USE SIGNAL ;
    SHAPE ABUTMENT ;
    PORT
      LAYER M4 ;
      RECT 0.000 26.352 0.036 26.376 ;
    END
  END wd_in[142]
  PIN wd_in[143]
    DIRECTION INPUT ;
    USE SIGNAL ;
    SHAPE ABUTMENT ;
    PORT
      LAYER M4 ;
      RECT 0.000 26.400 0.036 26.424 ;
    END
  END wd_in[143]
  PIN wd_in[144]
    DIRECTION INPUT ;
    USE SIGNAL ;
    SHAPE ABUTMENT ;
    PORT
      LAYER M4 ;
      RECT 0.000 26.448 0.036 26.472 ;
    END
  END wd_in[144]
  PIN wd_in[145]
    DIRECTION INPUT ;
    USE SIGNAL ;
    SHAPE ABUTMENT ;
    PORT
      LAYER M4 ;
      RECT 0.000 26.496 0.036 26.520 ;
    END
  END wd_in[145]
  PIN wd_in[146]
    DIRECTION INPUT ;
    USE SIGNAL ;
    SHAPE ABUTMENT ;
    PORT
      LAYER M4 ;
      RECT 0.000 26.544 0.036 26.568 ;
    END
  END wd_in[146]
  PIN wd_in[147]
    DIRECTION INPUT ;
    USE SIGNAL ;
    SHAPE ABUTMENT ;
    PORT
      LAYER M4 ;
      RECT 0.000 26.592 0.036 26.616 ;
    END
  END wd_in[147]
  PIN wd_in[148]
    DIRECTION INPUT ;
    USE SIGNAL ;
    SHAPE ABUTMENT ;
    PORT
      LAYER M4 ;
      RECT 0.000 26.640 0.036 26.664 ;
    END
  END wd_in[148]
  PIN wd_in[149]
    DIRECTION INPUT ;
    USE SIGNAL ;
    SHAPE ABUTMENT ;
    PORT
      LAYER M4 ;
      RECT 0.000 26.688 0.036 26.712 ;
    END
  END wd_in[149]
  PIN wd_in[150]
    DIRECTION INPUT ;
    USE SIGNAL ;
    SHAPE ABUTMENT ;
    PORT
      LAYER M4 ;
      RECT 0.000 26.736 0.036 26.760 ;
    END
  END wd_in[150]
  PIN wd_in[151]
    DIRECTION INPUT ;
    USE SIGNAL ;
    SHAPE ABUTMENT ;
    PORT
      LAYER M4 ;
      RECT 0.000 26.784 0.036 26.808 ;
    END
  END wd_in[151]
  PIN wd_in[152]
    DIRECTION INPUT ;
    USE SIGNAL ;
    SHAPE ABUTMENT ;
    PORT
      LAYER M4 ;
      RECT 0.000 26.832 0.036 26.856 ;
    END
  END wd_in[152]
  PIN wd_in[153]
    DIRECTION INPUT ;
    USE SIGNAL ;
    SHAPE ABUTMENT ;
    PORT
      LAYER M4 ;
      RECT 0.000 26.880 0.036 26.904 ;
    END
  END wd_in[153]
  PIN wd_in[154]
    DIRECTION INPUT ;
    USE SIGNAL ;
    SHAPE ABUTMENT ;
    PORT
      LAYER M4 ;
      RECT 0.000 26.928 0.036 26.952 ;
    END
  END wd_in[154]
  PIN wd_in[155]
    DIRECTION INPUT ;
    USE SIGNAL ;
    SHAPE ABUTMENT ;
    PORT
      LAYER M4 ;
      RECT 0.000 26.976 0.036 27.000 ;
    END
  END wd_in[155]
  PIN wd_in[156]
    DIRECTION INPUT ;
    USE SIGNAL ;
    SHAPE ABUTMENT ;
    PORT
      LAYER M4 ;
      RECT 0.000 27.024 0.036 27.048 ;
    END
  END wd_in[156]
  PIN wd_in[157]
    DIRECTION INPUT ;
    USE SIGNAL ;
    SHAPE ABUTMENT ;
    PORT
      LAYER M4 ;
      RECT 0.000 27.072 0.036 27.096 ;
    END
  END wd_in[157]
  PIN wd_in[158]
    DIRECTION INPUT ;
    USE SIGNAL ;
    SHAPE ABUTMENT ;
    PORT
      LAYER M4 ;
      RECT 0.000 27.120 0.036 27.144 ;
    END
  END wd_in[158]
  PIN wd_in[159]
    DIRECTION INPUT ;
    USE SIGNAL ;
    SHAPE ABUTMENT ;
    PORT
      LAYER M4 ;
      RECT 0.000 27.168 0.036 27.192 ;
    END
  END wd_in[159]
  PIN wd_in[160]
    DIRECTION INPUT ;
    USE SIGNAL ;
    SHAPE ABUTMENT ;
    PORT
      LAYER M4 ;
      RECT 0.000 27.216 0.036 27.240 ;
    END
  END wd_in[160]
  PIN wd_in[161]
    DIRECTION INPUT ;
    USE SIGNAL ;
    SHAPE ABUTMENT ;
    PORT
      LAYER M4 ;
      RECT 0.000 27.264 0.036 27.288 ;
    END
  END wd_in[161]
  PIN wd_in[162]
    DIRECTION INPUT ;
    USE SIGNAL ;
    SHAPE ABUTMENT ;
    PORT
      LAYER M4 ;
      RECT 0.000 27.312 0.036 27.336 ;
    END
  END wd_in[162]
  PIN wd_in[163]
    DIRECTION INPUT ;
    USE SIGNAL ;
    SHAPE ABUTMENT ;
    PORT
      LAYER M4 ;
      RECT 0.000 27.360 0.036 27.384 ;
    END
  END wd_in[163]
  PIN wd_in[164]
    DIRECTION INPUT ;
    USE SIGNAL ;
    SHAPE ABUTMENT ;
    PORT
      LAYER M4 ;
      RECT 0.000 27.408 0.036 27.432 ;
    END
  END wd_in[164]
  PIN wd_in[165]
    DIRECTION INPUT ;
    USE SIGNAL ;
    SHAPE ABUTMENT ;
    PORT
      LAYER M4 ;
      RECT 0.000 27.456 0.036 27.480 ;
    END
  END wd_in[165]
  PIN wd_in[166]
    DIRECTION INPUT ;
    USE SIGNAL ;
    SHAPE ABUTMENT ;
    PORT
      LAYER M4 ;
      RECT 0.000 27.504 0.036 27.528 ;
    END
  END wd_in[166]
  PIN wd_in[167]
    DIRECTION INPUT ;
    USE SIGNAL ;
    SHAPE ABUTMENT ;
    PORT
      LAYER M4 ;
      RECT 0.000 27.552 0.036 27.576 ;
    END
  END wd_in[167]
  PIN wd_in[168]
    DIRECTION INPUT ;
    USE SIGNAL ;
    SHAPE ABUTMENT ;
    PORT
      LAYER M4 ;
      RECT 0.000 27.600 0.036 27.624 ;
    END
  END wd_in[168]
  PIN wd_in[169]
    DIRECTION INPUT ;
    USE SIGNAL ;
    SHAPE ABUTMENT ;
    PORT
      LAYER M4 ;
      RECT 0.000 27.648 0.036 27.672 ;
    END
  END wd_in[169]
  PIN wd_in[170]
    DIRECTION INPUT ;
    USE SIGNAL ;
    SHAPE ABUTMENT ;
    PORT
      LAYER M4 ;
      RECT 0.000 27.696 0.036 27.720 ;
    END
  END wd_in[170]
  PIN wd_in[171]
    DIRECTION INPUT ;
    USE SIGNAL ;
    SHAPE ABUTMENT ;
    PORT
      LAYER M4 ;
      RECT 0.000 27.744 0.036 27.768 ;
    END
  END wd_in[171]
  PIN wd_in[172]
    DIRECTION INPUT ;
    USE SIGNAL ;
    SHAPE ABUTMENT ;
    PORT
      LAYER M4 ;
      RECT 0.000 27.792 0.036 27.816 ;
    END
  END wd_in[172]
  PIN wd_in[173]
    DIRECTION INPUT ;
    USE SIGNAL ;
    SHAPE ABUTMENT ;
    PORT
      LAYER M4 ;
      RECT 0.000 27.840 0.036 27.864 ;
    END
  END wd_in[173]
  PIN wd_in[174]
    DIRECTION INPUT ;
    USE SIGNAL ;
    SHAPE ABUTMENT ;
    PORT
      LAYER M4 ;
      RECT 0.000 27.888 0.036 27.912 ;
    END
  END wd_in[174]
  PIN wd_in[175]
    DIRECTION INPUT ;
    USE SIGNAL ;
    SHAPE ABUTMENT ;
    PORT
      LAYER M4 ;
      RECT 0.000 27.936 0.036 27.960 ;
    END
  END wd_in[175]
  PIN wd_in[176]
    DIRECTION INPUT ;
    USE SIGNAL ;
    SHAPE ABUTMENT ;
    PORT
      LAYER M4 ;
      RECT 0.000 27.984 0.036 28.008 ;
    END
  END wd_in[176]
  PIN wd_in[177]
    DIRECTION INPUT ;
    USE SIGNAL ;
    SHAPE ABUTMENT ;
    PORT
      LAYER M4 ;
      RECT 0.000 28.032 0.036 28.056 ;
    END
  END wd_in[177]
  PIN wd_in[178]
    DIRECTION INPUT ;
    USE SIGNAL ;
    SHAPE ABUTMENT ;
    PORT
      LAYER M4 ;
      RECT 0.000 28.080 0.036 28.104 ;
    END
  END wd_in[178]
  PIN wd_in[179]
    DIRECTION INPUT ;
    USE SIGNAL ;
    SHAPE ABUTMENT ;
    PORT
      LAYER M4 ;
      RECT 0.000 28.128 0.036 28.152 ;
    END
  END wd_in[179]
  PIN wd_in[180]
    DIRECTION INPUT ;
    USE SIGNAL ;
    SHAPE ABUTMENT ;
    PORT
      LAYER M4 ;
      RECT 0.000 28.176 0.036 28.200 ;
    END
  END wd_in[180]
  PIN wd_in[181]
    DIRECTION INPUT ;
    USE SIGNAL ;
    SHAPE ABUTMENT ;
    PORT
      LAYER M4 ;
      RECT 0.000 28.224 0.036 28.248 ;
    END
  END wd_in[181]
  PIN wd_in[182]
    DIRECTION INPUT ;
    USE SIGNAL ;
    SHAPE ABUTMENT ;
    PORT
      LAYER M4 ;
      RECT 0.000 28.272 0.036 28.296 ;
    END
  END wd_in[182]
  PIN wd_in[183]
    DIRECTION INPUT ;
    USE SIGNAL ;
    SHAPE ABUTMENT ;
    PORT
      LAYER M4 ;
      RECT 0.000 28.320 0.036 28.344 ;
    END
  END wd_in[183]
  PIN wd_in[184]
    DIRECTION INPUT ;
    USE SIGNAL ;
    SHAPE ABUTMENT ;
    PORT
      LAYER M4 ;
      RECT 0.000 28.368 0.036 28.392 ;
    END
  END wd_in[184]
  PIN wd_in[185]
    DIRECTION INPUT ;
    USE SIGNAL ;
    SHAPE ABUTMENT ;
    PORT
      LAYER M4 ;
      RECT 0.000 28.416 0.036 28.440 ;
    END
  END wd_in[185]
  PIN wd_in[186]
    DIRECTION INPUT ;
    USE SIGNAL ;
    SHAPE ABUTMENT ;
    PORT
      LAYER M4 ;
      RECT 0.000 28.464 0.036 28.488 ;
    END
  END wd_in[186]
  PIN wd_in[187]
    DIRECTION INPUT ;
    USE SIGNAL ;
    SHAPE ABUTMENT ;
    PORT
      LAYER M4 ;
      RECT 0.000 28.512 0.036 28.536 ;
    END
  END wd_in[187]
  PIN wd_in[188]
    DIRECTION INPUT ;
    USE SIGNAL ;
    SHAPE ABUTMENT ;
    PORT
      LAYER M4 ;
      RECT 0.000 28.560 0.036 28.584 ;
    END
  END wd_in[188]
  PIN wd_in[189]
    DIRECTION INPUT ;
    USE SIGNAL ;
    SHAPE ABUTMENT ;
    PORT
      LAYER M4 ;
      RECT 0.000 28.608 0.036 28.632 ;
    END
  END wd_in[189]
  PIN wd_in[190]
    DIRECTION INPUT ;
    USE SIGNAL ;
    SHAPE ABUTMENT ;
    PORT
      LAYER M4 ;
      RECT 0.000 28.656 0.036 28.680 ;
    END
  END wd_in[190]
  PIN wd_in[191]
    DIRECTION INPUT ;
    USE SIGNAL ;
    SHAPE ABUTMENT ;
    PORT
      LAYER M4 ;
      RECT 0.000 28.704 0.036 28.728 ;
    END
  END wd_in[191]
  PIN wd_in[192]
    DIRECTION INPUT ;
    USE SIGNAL ;
    SHAPE ABUTMENT ;
    PORT
      LAYER M4 ;
      RECT 0.000 28.752 0.036 28.776 ;
    END
  END wd_in[192]
  PIN wd_in[193]
    DIRECTION INPUT ;
    USE SIGNAL ;
    SHAPE ABUTMENT ;
    PORT
      LAYER M4 ;
      RECT 0.000 28.800 0.036 28.824 ;
    END
  END wd_in[193]
  PIN wd_in[194]
    DIRECTION INPUT ;
    USE SIGNAL ;
    SHAPE ABUTMENT ;
    PORT
      LAYER M4 ;
      RECT 0.000 28.848 0.036 28.872 ;
    END
  END wd_in[194]
  PIN wd_in[195]
    DIRECTION INPUT ;
    USE SIGNAL ;
    SHAPE ABUTMENT ;
    PORT
      LAYER M4 ;
      RECT 0.000 28.896 0.036 28.920 ;
    END
  END wd_in[195]
  PIN wd_in[196]
    DIRECTION INPUT ;
    USE SIGNAL ;
    SHAPE ABUTMENT ;
    PORT
      LAYER M4 ;
      RECT 0.000 28.944 0.036 28.968 ;
    END
  END wd_in[196]
  PIN wd_in[197]
    DIRECTION INPUT ;
    USE SIGNAL ;
    SHAPE ABUTMENT ;
    PORT
      LAYER M4 ;
      RECT 0.000 28.992 0.036 29.016 ;
    END
  END wd_in[197]
  PIN wd_in[198]
    DIRECTION INPUT ;
    USE SIGNAL ;
    SHAPE ABUTMENT ;
    PORT
      LAYER M4 ;
      RECT 0.000 29.040 0.036 29.064 ;
    END
  END wd_in[198]
  PIN wd_in[199]
    DIRECTION INPUT ;
    USE SIGNAL ;
    SHAPE ABUTMENT ;
    PORT
      LAYER M4 ;
      RECT 0.000 29.088 0.036 29.112 ;
    END
  END wd_in[199]
  PIN wd_in[200]
    DIRECTION INPUT ;
    USE SIGNAL ;
    SHAPE ABUTMENT ;
    PORT
      LAYER M4 ;
      RECT 0.000 29.136 0.036 29.160 ;
    END
  END wd_in[200]
  PIN wd_in[201]
    DIRECTION INPUT ;
    USE SIGNAL ;
    SHAPE ABUTMENT ;
    PORT
      LAYER M4 ;
      RECT 0.000 29.184 0.036 29.208 ;
    END
  END wd_in[201]
  PIN wd_in[202]
    DIRECTION INPUT ;
    USE SIGNAL ;
    SHAPE ABUTMENT ;
    PORT
      LAYER M4 ;
      RECT 0.000 29.232 0.036 29.256 ;
    END
  END wd_in[202]
  PIN wd_in[203]
    DIRECTION INPUT ;
    USE SIGNAL ;
    SHAPE ABUTMENT ;
    PORT
      LAYER M4 ;
      RECT 0.000 29.280 0.036 29.304 ;
    END
  END wd_in[203]
  PIN wd_in[204]
    DIRECTION INPUT ;
    USE SIGNAL ;
    SHAPE ABUTMENT ;
    PORT
      LAYER M4 ;
      RECT 0.000 29.328 0.036 29.352 ;
    END
  END wd_in[204]
  PIN wd_in[205]
    DIRECTION INPUT ;
    USE SIGNAL ;
    SHAPE ABUTMENT ;
    PORT
      LAYER M4 ;
      RECT 0.000 29.376 0.036 29.400 ;
    END
  END wd_in[205]
  PIN wd_in[206]
    DIRECTION INPUT ;
    USE SIGNAL ;
    SHAPE ABUTMENT ;
    PORT
      LAYER M4 ;
      RECT 0.000 29.424 0.036 29.448 ;
    END
  END wd_in[206]
  PIN wd_in[207]
    DIRECTION INPUT ;
    USE SIGNAL ;
    SHAPE ABUTMENT ;
    PORT
      LAYER M4 ;
      RECT 0.000 29.472 0.036 29.496 ;
    END
  END wd_in[207]
  PIN wd_in[208]
    DIRECTION INPUT ;
    USE SIGNAL ;
    SHAPE ABUTMENT ;
    PORT
      LAYER M4 ;
      RECT 0.000 29.520 0.036 29.544 ;
    END
  END wd_in[208]
  PIN wd_in[209]
    DIRECTION INPUT ;
    USE SIGNAL ;
    SHAPE ABUTMENT ;
    PORT
      LAYER M4 ;
      RECT 0.000 29.568 0.036 29.592 ;
    END
  END wd_in[209]
  PIN wd_in[210]
    DIRECTION INPUT ;
    USE SIGNAL ;
    SHAPE ABUTMENT ;
    PORT
      LAYER M4 ;
      RECT 0.000 29.616 0.036 29.640 ;
    END
  END wd_in[210]
  PIN wd_in[211]
    DIRECTION INPUT ;
    USE SIGNAL ;
    SHAPE ABUTMENT ;
    PORT
      LAYER M4 ;
      RECT 0.000 29.664 0.036 29.688 ;
    END
  END wd_in[211]
  PIN wd_in[212]
    DIRECTION INPUT ;
    USE SIGNAL ;
    SHAPE ABUTMENT ;
    PORT
      LAYER M4 ;
      RECT 0.000 29.712 0.036 29.736 ;
    END
  END wd_in[212]
  PIN wd_in[213]
    DIRECTION INPUT ;
    USE SIGNAL ;
    SHAPE ABUTMENT ;
    PORT
      LAYER M4 ;
      RECT 0.000 29.760 0.036 29.784 ;
    END
  END wd_in[213]
  PIN wd_in[214]
    DIRECTION INPUT ;
    USE SIGNAL ;
    SHAPE ABUTMENT ;
    PORT
      LAYER M4 ;
      RECT 0.000 29.808 0.036 29.832 ;
    END
  END wd_in[214]
  PIN wd_in[215]
    DIRECTION INPUT ;
    USE SIGNAL ;
    SHAPE ABUTMENT ;
    PORT
      LAYER M4 ;
      RECT 0.000 29.856 0.036 29.880 ;
    END
  END wd_in[215]
  PIN wd_in[216]
    DIRECTION INPUT ;
    USE SIGNAL ;
    SHAPE ABUTMENT ;
    PORT
      LAYER M4 ;
      RECT 0.000 29.904 0.036 29.928 ;
    END
  END wd_in[216]
  PIN wd_in[217]
    DIRECTION INPUT ;
    USE SIGNAL ;
    SHAPE ABUTMENT ;
    PORT
      LAYER M4 ;
      RECT 0.000 29.952 0.036 29.976 ;
    END
  END wd_in[217]
  PIN wd_in[218]
    DIRECTION INPUT ;
    USE SIGNAL ;
    SHAPE ABUTMENT ;
    PORT
      LAYER M4 ;
      RECT 0.000 30.000 0.036 30.024 ;
    END
  END wd_in[218]
  PIN wd_in[219]
    DIRECTION INPUT ;
    USE SIGNAL ;
    SHAPE ABUTMENT ;
    PORT
      LAYER M4 ;
      RECT 0.000 30.048 0.036 30.072 ;
    END
  END wd_in[219]
  PIN wd_in[220]
    DIRECTION INPUT ;
    USE SIGNAL ;
    SHAPE ABUTMENT ;
    PORT
      LAYER M4 ;
      RECT 0.000 30.096 0.036 30.120 ;
    END
  END wd_in[220]
  PIN wd_in[221]
    DIRECTION INPUT ;
    USE SIGNAL ;
    SHAPE ABUTMENT ;
    PORT
      LAYER M4 ;
      RECT 0.000 30.144 0.036 30.168 ;
    END
  END wd_in[221]
  PIN wd_in[222]
    DIRECTION INPUT ;
    USE SIGNAL ;
    SHAPE ABUTMENT ;
    PORT
      LAYER M4 ;
      RECT 0.000 30.192 0.036 30.216 ;
    END
  END wd_in[222]
  PIN wd_in[223]
    DIRECTION INPUT ;
    USE SIGNAL ;
    SHAPE ABUTMENT ;
    PORT
      LAYER M4 ;
      RECT 0.000 30.240 0.036 30.264 ;
    END
  END wd_in[223]
  PIN wd_in[224]
    DIRECTION INPUT ;
    USE SIGNAL ;
    SHAPE ABUTMENT ;
    PORT
      LAYER M4 ;
      RECT 0.000 30.288 0.036 30.312 ;
    END
  END wd_in[224]
  PIN wd_in[225]
    DIRECTION INPUT ;
    USE SIGNAL ;
    SHAPE ABUTMENT ;
    PORT
      LAYER M4 ;
      RECT 0.000 30.336 0.036 30.360 ;
    END
  END wd_in[225]
  PIN wd_in[226]
    DIRECTION INPUT ;
    USE SIGNAL ;
    SHAPE ABUTMENT ;
    PORT
      LAYER M4 ;
      RECT 0.000 30.384 0.036 30.408 ;
    END
  END wd_in[226]
  PIN wd_in[227]
    DIRECTION INPUT ;
    USE SIGNAL ;
    SHAPE ABUTMENT ;
    PORT
      LAYER M4 ;
      RECT 0.000 30.432 0.036 30.456 ;
    END
  END wd_in[227]
  PIN wd_in[228]
    DIRECTION INPUT ;
    USE SIGNAL ;
    SHAPE ABUTMENT ;
    PORT
      LAYER M4 ;
      RECT 0.000 30.480 0.036 30.504 ;
    END
  END wd_in[228]
  PIN wd_in[229]
    DIRECTION INPUT ;
    USE SIGNAL ;
    SHAPE ABUTMENT ;
    PORT
      LAYER M4 ;
      RECT 0.000 30.528 0.036 30.552 ;
    END
  END wd_in[229]
  PIN wd_in[230]
    DIRECTION INPUT ;
    USE SIGNAL ;
    SHAPE ABUTMENT ;
    PORT
      LAYER M4 ;
      RECT 0.000 30.576 0.036 30.600 ;
    END
  END wd_in[230]
  PIN wd_in[231]
    DIRECTION INPUT ;
    USE SIGNAL ;
    SHAPE ABUTMENT ;
    PORT
      LAYER M4 ;
      RECT 0.000 30.624 0.036 30.648 ;
    END
  END wd_in[231]
  PIN wd_in[232]
    DIRECTION INPUT ;
    USE SIGNAL ;
    SHAPE ABUTMENT ;
    PORT
      LAYER M4 ;
      RECT 0.000 30.672 0.036 30.696 ;
    END
  END wd_in[232]
  PIN wd_in[233]
    DIRECTION INPUT ;
    USE SIGNAL ;
    SHAPE ABUTMENT ;
    PORT
      LAYER M4 ;
      RECT 0.000 30.720 0.036 30.744 ;
    END
  END wd_in[233]
  PIN wd_in[234]
    DIRECTION INPUT ;
    USE SIGNAL ;
    SHAPE ABUTMENT ;
    PORT
      LAYER M4 ;
      RECT 0.000 30.768 0.036 30.792 ;
    END
  END wd_in[234]
  PIN wd_in[235]
    DIRECTION INPUT ;
    USE SIGNAL ;
    SHAPE ABUTMENT ;
    PORT
      LAYER M4 ;
      RECT 0.000 30.816 0.036 30.840 ;
    END
  END wd_in[235]
  PIN wd_in[236]
    DIRECTION INPUT ;
    USE SIGNAL ;
    SHAPE ABUTMENT ;
    PORT
      LAYER M4 ;
      RECT 0.000 30.864 0.036 30.888 ;
    END
  END wd_in[236]
  PIN wd_in[237]
    DIRECTION INPUT ;
    USE SIGNAL ;
    SHAPE ABUTMENT ;
    PORT
      LAYER M4 ;
      RECT 0.000 30.912 0.036 30.936 ;
    END
  END wd_in[237]
  PIN wd_in[238]
    DIRECTION INPUT ;
    USE SIGNAL ;
    SHAPE ABUTMENT ;
    PORT
      LAYER M4 ;
      RECT 0.000 30.960 0.036 30.984 ;
    END
  END wd_in[238]
  PIN wd_in[239]
    DIRECTION INPUT ;
    USE SIGNAL ;
    SHAPE ABUTMENT ;
    PORT
      LAYER M4 ;
      RECT 0.000 31.008 0.036 31.032 ;
    END
  END wd_in[239]
  PIN wd_in[240]
    DIRECTION INPUT ;
    USE SIGNAL ;
    SHAPE ABUTMENT ;
    PORT
      LAYER M4 ;
      RECT 0.000 31.056 0.036 31.080 ;
    END
  END wd_in[240]
  PIN wd_in[241]
    DIRECTION INPUT ;
    USE SIGNAL ;
    SHAPE ABUTMENT ;
    PORT
      LAYER M4 ;
      RECT 0.000 31.104 0.036 31.128 ;
    END
  END wd_in[241]
  PIN wd_in[242]
    DIRECTION INPUT ;
    USE SIGNAL ;
    SHAPE ABUTMENT ;
    PORT
      LAYER M4 ;
      RECT 0.000 31.152 0.036 31.176 ;
    END
  END wd_in[242]
  PIN wd_in[243]
    DIRECTION INPUT ;
    USE SIGNAL ;
    SHAPE ABUTMENT ;
    PORT
      LAYER M4 ;
      RECT 0.000 31.200 0.036 31.224 ;
    END
  END wd_in[243]
  PIN wd_in[244]
    DIRECTION INPUT ;
    USE SIGNAL ;
    SHAPE ABUTMENT ;
    PORT
      LAYER M4 ;
      RECT 0.000 31.248 0.036 31.272 ;
    END
  END wd_in[244]
  PIN wd_in[245]
    DIRECTION INPUT ;
    USE SIGNAL ;
    SHAPE ABUTMENT ;
    PORT
      LAYER M4 ;
      RECT 0.000 31.296 0.036 31.320 ;
    END
  END wd_in[245]
  PIN wd_in[246]
    DIRECTION INPUT ;
    USE SIGNAL ;
    SHAPE ABUTMENT ;
    PORT
      LAYER M4 ;
      RECT 0.000 31.344 0.036 31.368 ;
    END
  END wd_in[246]
  PIN wd_in[247]
    DIRECTION INPUT ;
    USE SIGNAL ;
    SHAPE ABUTMENT ;
    PORT
      LAYER M4 ;
      RECT 0.000 31.392 0.036 31.416 ;
    END
  END wd_in[247]
  PIN wd_in[248]
    DIRECTION INPUT ;
    USE SIGNAL ;
    SHAPE ABUTMENT ;
    PORT
      LAYER M4 ;
      RECT 0.000 31.440 0.036 31.464 ;
    END
  END wd_in[248]
  PIN wd_in[249]
    DIRECTION INPUT ;
    USE SIGNAL ;
    SHAPE ABUTMENT ;
    PORT
      LAYER M4 ;
      RECT 0.000 31.488 0.036 31.512 ;
    END
  END wd_in[249]
  PIN wd_in[250]
    DIRECTION INPUT ;
    USE SIGNAL ;
    SHAPE ABUTMENT ;
    PORT
      LAYER M4 ;
      RECT 0.000 31.536 0.036 31.560 ;
    END
  END wd_in[250]
  PIN wd_in[251]
    DIRECTION INPUT ;
    USE SIGNAL ;
    SHAPE ABUTMENT ;
    PORT
      LAYER M4 ;
      RECT 0.000 31.584 0.036 31.608 ;
    END
  END wd_in[251]
  PIN wd_in[252]
    DIRECTION INPUT ;
    USE SIGNAL ;
    SHAPE ABUTMENT ;
    PORT
      LAYER M4 ;
      RECT 0.000 31.632 0.036 31.656 ;
    END
  END wd_in[252]
  PIN wd_in[253]
    DIRECTION INPUT ;
    USE SIGNAL ;
    SHAPE ABUTMENT ;
    PORT
      LAYER M4 ;
      RECT 0.000 31.680 0.036 31.704 ;
    END
  END wd_in[253]
  PIN wd_in[254]
    DIRECTION INPUT ;
    USE SIGNAL ;
    SHAPE ABUTMENT ;
    PORT
      LAYER M4 ;
      RECT 0.000 31.728 0.036 31.752 ;
    END
  END wd_in[254]
  PIN wd_in[255]
    DIRECTION INPUT ;
    USE SIGNAL ;
    SHAPE ABUTMENT ;
    PORT
      LAYER M4 ;
      RECT 0.000 31.776 0.036 31.800 ;
    END
  END wd_in[255]
  PIN addr_in[0]
    DIRECTION INPUT ;
    USE SIGNAL ;
    SHAPE ABUTMENT ;
    PORT
      LAYER M4 ;
      RECT 0.000 39.024 0.036 39.048 ;
    END
  END addr_in[0]
  PIN addr_in[1]
    DIRECTION INPUT ;
    USE SIGNAL ;
    SHAPE ABUTMENT ;
    PORT
      LAYER M4 ;
      RECT 0.000 39.072 0.036 39.096 ;
    END
  END addr_in[1]
  PIN addr_in[2]
    DIRECTION INPUT ;
    USE SIGNAL ;
    SHAPE ABUTMENT ;
    PORT
      LAYER M4 ;
      RECT 0.000 39.120 0.036 39.144 ;
    END
  END addr_in[2]
  PIN addr_in[3]
    DIRECTION INPUT ;
    USE SIGNAL ;
    SHAPE ABUTMENT ;
    PORT
      LAYER M4 ;
      RECT 0.000 39.168 0.036 39.192 ;
    END
  END addr_in[3]
  PIN addr_in[4]
    DIRECTION INPUT ;
    USE SIGNAL ;
    SHAPE ABUTMENT ;
    PORT
      LAYER M4 ;
      RECT 0.000 39.216 0.036 39.240 ;
    END
  END addr_in[4]
  PIN addr_in[5]
    DIRECTION INPUT ;
    USE SIGNAL ;
    SHAPE ABUTMENT ;
    PORT
      LAYER M4 ;
      RECT 0.000 39.264 0.036 39.288 ;
    END
  END addr_in[5]
  PIN we_in
    DIRECTION INPUT ;
    USE SIGNAL ;
    SHAPE ABUTMENT ;
    PORT
      LAYER M4 ;
      RECT 0.000 46.512 0.036 46.536 ;
    END
  END we_in
  PIN ce_in
    DIRECTION INPUT ;
    USE SIGNAL ;
    SHAPE ABUTMENT ;
    PORT
      LAYER M4 ;
      RECT 0.000 46.560 0.036 46.584 ;
    END
  END ce_in
  PIN clk
    DIRECTION INPUT ;
    USE SIGNAL ;
    SHAPE ABUTMENT ;
    PORT
      LAYER M4 ;
      RECT 0.000 46.608 0.036 46.632 ;
    END
  END clk
  PIN VSS
    DIRECTION INOUT ;
    USE GROUND ;
    PORT
      LAYER M4 ;
      RECT 0.096 0.000 33.154 0.096 ;
      RECT 0.096 0.768 33.154 0.864 ;
      RECT 0.096 1.536 33.154 1.632 ;
      RECT 0.096 2.304 33.154 2.400 ;
      RECT 0.096 3.072 33.154 3.168 ;
      RECT 0.096 3.840 33.154 3.936 ;
      RECT 0.096 4.608 33.154 4.704 ;
      RECT 0.096 5.376 33.154 5.472 ;
      RECT 0.096 6.144 33.154 6.240 ;
      RECT 0.096 6.912 33.154 7.008 ;
      RECT 0.096 7.680 33.154 7.776 ;
      RECT 0.096 8.448 33.154 8.544 ;
      RECT 0.096 9.216 33.154 9.312 ;
      RECT 0.096 9.984 33.154 10.080 ;
      RECT 0.096 10.752 33.154 10.848 ;
      RECT 0.096 11.520 33.154 11.616 ;
      RECT 0.096 12.288 33.154 12.384 ;
      RECT 0.096 13.056 33.154 13.152 ;
      RECT 0.096 13.824 33.154 13.920 ;
      RECT 0.096 14.592 33.154 14.688 ;
      RECT 0.096 15.360 33.154 15.456 ;
      RECT 0.096 16.128 33.154 16.224 ;
      RECT 0.096 16.896 33.154 16.992 ;
      RECT 0.096 17.664 33.154 17.760 ;
      RECT 0.096 18.432 33.154 18.528 ;
      RECT 0.096 19.200 33.154 19.296 ;
      RECT 0.096 19.968 33.154 20.064 ;
      RECT 0.096 20.736 33.154 20.832 ;
      RECT 0.096 21.504 33.154 21.600 ;
      RECT 0.096 22.272 33.154 22.368 ;
      RECT 0.096 23.040 33.154 23.136 ;
      RECT 0.096 23.808 33.154 23.904 ;
      RECT 0.096 24.576 33.154 24.672 ;
      RECT 0.096 25.344 33.154 25.440 ;
      RECT 0.096 26.112 33.154 26.208 ;
      RECT 0.096 26.880 33.154 26.976 ;
      RECT 0.096 27.648 33.154 27.744 ;
      RECT 0.096 28.416 33.154 28.512 ;
      RECT 0.096 29.184 33.154 29.280 ;
      RECT 0.096 29.952 33.154 30.048 ;
      RECT 0.096 30.720 33.154 30.816 ;
      RECT 0.096 31.488 33.154 31.584 ;
      RECT 0.096 32.256 33.154 32.352 ;
      RECT 0.096 33.024 33.154 33.120 ;
      RECT 0.096 33.792 33.154 33.888 ;
      RECT 0.096 34.560 33.154 34.656 ;
      RECT 0.096 35.328 33.154 35.424 ;
      RECT 0.096 36.096 33.154 36.192 ;
      RECT 0.096 36.864 33.154 36.960 ;
      RECT 0.096 37.632 33.154 37.728 ;
      RECT 0.096 38.400 33.154 38.496 ;
      RECT 0.096 39.168 33.154 39.264 ;
      RECT 0.096 39.936 33.154 40.032 ;
      RECT 0.096 40.704 33.154 40.800 ;
      RECT 0.096 41.472 33.154 41.568 ;
      RECT 0.096 42.240 33.154 42.336 ;
      RECT 0.096 43.008 33.154 43.104 ;
      RECT 0.096 43.776 33.154 43.872 ;
      RECT 0.096 44.544 33.154 44.640 ;
      RECT 0.096 45.312 33.154 45.408 ;
      RECT 0.096 46.080 33.154 46.176 ;
    END
  END VSS
  PIN VDD
    DIRECTION INOUT ;
    USE POWER ;
    PORT
      LAYER M4 ;
      RECT 0.096 0.384 33.154 0.480 ;
      RECT 0.096 1.152 33.154 1.248 ;
      RECT 0.096 1.920 33.154 2.016 ;
      RECT 0.096 2.688 33.154 2.784 ;
      RECT 0.096 3.456 33.154 3.552 ;
      RECT 0.096 4.224 33.154 4.320 ;
      RECT 0.096 4.992 33.154 5.088 ;
      RECT 0.096 5.760 33.154 5.856 ;
      RECT 0.096 6.528 33.154 6.624 ;
      RECT 0.096 7.296 33.154 7.392 ;
      RECT 0.096 8.064 33.154 8.160 ;
      RECT 0.096 8.832 33.154 8.928 ;
      RECT 0.096 9.600 33.154 9.696 ;
      RECT 0.096 10.368 33.154 10.464 ;
      RECT 0.096 11.136 33.154 11.232 ;
      RECT 0.096 11.904 33.154 12.000 ;
      RECT 0.096 12.672 33.154 12.768 ;
      RECT 0.096 13.440 33.154 13.536 ;
      RECT 0.096 14.208 33.154 14.304 ;
      RECT 0.096 14.976 33.154 15.072 ;
      RECT 0.096 15.744 33.154 15.840 ;
      RECT 0.096 16.512 33.154 16.608 ;
      RECT 0.096 17.280 33.154 17.376 ;
      RECT 0.096 18.048 33.154 18.144 ;
      RECT 0.096 18.816 33.154 18.912 ;
      RECT 0.096 19.584 33.154 19.680 ;
      RECT 0.096 20.352 33.154 20.448 ;
      RECT 0.096 21.120 33.154 21.216 ;
      RECT 0.096 21.888 33.154 21.984 ;
      RECT 0.096 22.656 33.154 22.752 ;
      RECT 0.096 23.424 33.154 23.520 ;
      RECT 0.096 24.192 33.154 24.288 ;
      RECT 0.096 24.960 33.154 25.056 ;
      RECT 0.096 25.728 33.154 25.824 ;
      RECT 0.096 26.496 33.154 26.592 ;
      RECT 0.096 27.264 33.154 27.360 ;
      RECT 0.096 28.032 33.154 28.128 ;
      RECT 0.096 28.800 33.154 28.896 ;
      RECT 0.096 29.568 33.154 29.664 ;
      RECT 0.096 30.336 33.154 30.432 ;
      RECT 0.096 31.104 33.154 31.200 ;
      RECT 0.096 31.872 33.154 31.968 ;
      RECT 0.096 32.640 33.154 32.736 ;
      RECT 0.096 33.408 33.154 33.504 ;
      RECT 0.096 34.176 33.154 34.272 ;
      RECT 0.096 34.944 33.154 35.040 ;
      RECT 0.096 35.712 33.154 35.808 ;
      RECT 0.096 36.480 33.154 36.576 ;
      RECT 0.096 37.248 33.154 37.344 ;
      RECT 0.096 38.016 33.154 38.112 ;
      RECT 0.096 38.784 33.154 38.880 ;
      RECT 0.096 39.552 33.154 39.648 ;
      RECT 0.096 40.320 33.154 40.416 ;
      RECT 0.096 41.088 33.154 41.184 ;
      RECT 0.096 41.856 33.154 41.952 ;
      RECT 0.096 42.624 33.154 42.720 ;
      RECT 0.096 43.392 33.154 43.488 ;
      RECT 0.096 44.160 33.154 44.256 ;
      RECT 0.096 44.928 33.154 45.024 ;
      RECT 0.096 45.696 33.154 45.792 ;
      RECT 0.096 46.464 33.154 46.560 ;
    END
  END VDD
  OBS
    LAYER M1 ;
    RECT 0 0 33.250 46.800 ;
    LAYER M2 ;
    RECT 0 0 33.250 46.800 ;
    LAYER M3 ;
    RECT 0 0 33.250 46.800 ;
    LAYER M4 ;
    RECT 0 0 33.250 46.800 ;
  END
END fakeram7_64x256

END LIBRARY
